VERSION 5.7 ;
  NOWIREEXTENSIONATPIN ON ;
  DIVIDERCHAR "/" ;
  BUSBITCHARS "[]" ;
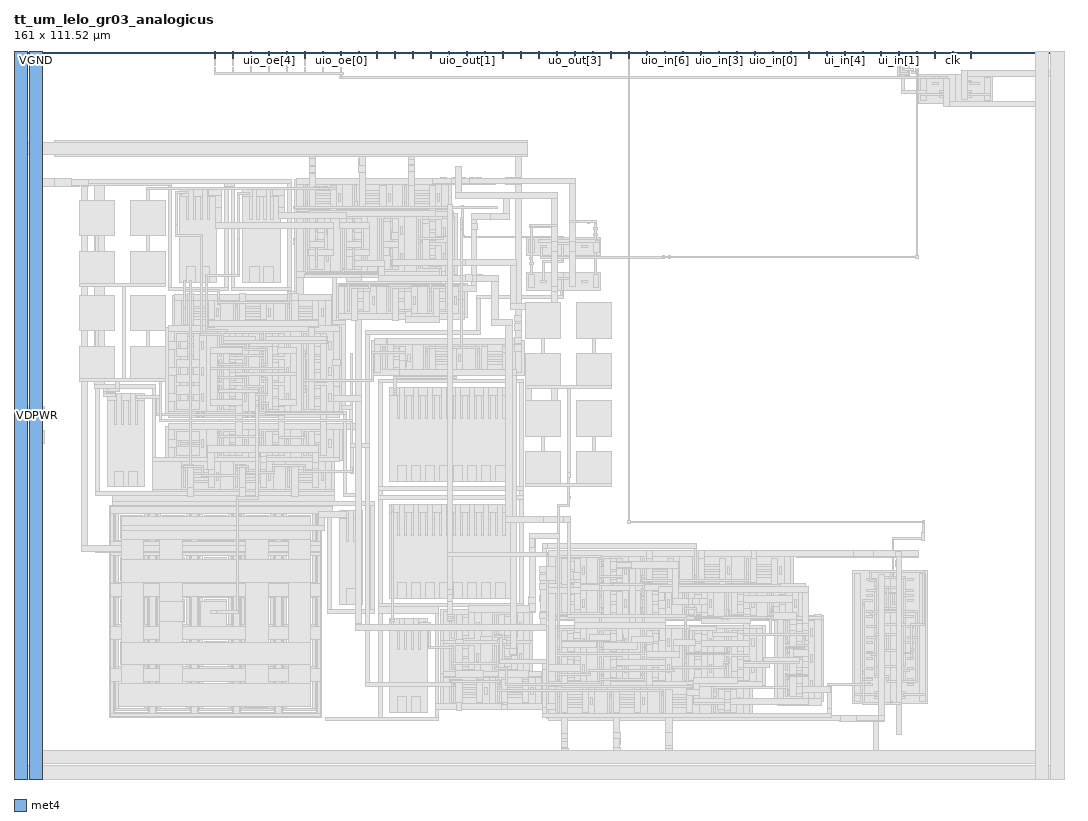
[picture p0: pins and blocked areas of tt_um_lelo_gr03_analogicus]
MACRO tt_um_lelo_gr03_analogicus
  CLASS BLOCK ;
  FOREIGN tt_um_lelo_gr03_analogicus ;
  ORIGIN 0.000 0.000 ;
  SIZE 161.000 BY 111.520 ;
  PIN uo_out[7]
    DIRECTION OUTPUT ;
    USE SIGNAL ;
    PORT
      LAYER met4 ;
        RECT 74.830 110.520 75.130 111.520 ;
    END
  END uo_out[7]
  PIN uo_out[6]
    DIRECTION OUTPUT ;
    USE SIGNAL ;
    PORT
      LAYER met4 ;
        RECT 77.590 110.520 77.890 111.520 ;
    END
  END uo_out[6]
  PIN uo_out[5]
    DIRECTION OUTPUT ;
    USE SIGNAL ;
    PORT
      LAYER met4 ;
        RECT 80.350 110.520 80.650 111.520 ;
    END
  END uo_out[5]
  PIN uo_out[4]
    DIRECTION OUTPUT ;
    USE SIGNAL ;
    PORT
      LAYER met4 ;
        RECT 83.110 110.520 83.410 111.520 ;
    END
  END uo_out[4]
  PIN uo_out[3]
    DIRECTION OUTPUT ;
    USE SIGNAL ;
    PORT
      LAYER met4 ;
        RECT 85.870 110.520 86.170 111.520 ;
    END
  END uo_out[3]
  PIN uo_out[2]
    DIRECTION OUTPUT ;
    USE SIGNAL ;
    PORT
      LAYER met4 ;
        RECT 88.630 110.520 88.930 111.520 ;
    END
  END uo_out[2]
  PIN uo_out[1]
    DIRECTION OUTPUT ;
    USE SIGNAL ;
    PORT
      LAYER met4 ;
        RECT 91.390 110.520 91.690 111.520 ;
    END
  END uo_out[1]
  PIN uo_out[0]
    DIRECTION OUTPUT ;
    USE SIGNAL ;
    ANTENNAGATEAREA 0.288000 ;
    ANTENNADIFFAREA 0.936000 ;
    PORT
      LAYER met4 ;
        RECT 94.150 110.520 94.450 111.520 ;
    END
  END uo_out[0]
  PIN uio_out[7]
    DIRECTION OUTPUT ;
    USE SIGNAL ;
    PORT
      LAYER met4 ;
        RECT 52.750 110.520 53.050 111.520 ;
    END
  END uio_out[7]
  PIN uio_out[6]
    DIRECTION OUTPUT ;
    USE SIGNAL ;
    PORT
      LAYER met4 ;
        RECT 55.510 110.520 55.810 111.520 ;
    END
  END uio_out[6]
  PIN uio_out[5]
    DIRECTION OUTPUT ;
    USE SIGNAL ;
    PORT
      LAYER met4 ;
        RECT 58.270 110.520 58.570 111.520 ;
    END
  END uio_out[5]
  PIN uio_out[4]
    DIRECTION OUTPUT ;
    USE SIGNAL ;
    PORT
      LAYER met4 ;
        RECT 61.030 110.520 61.330 111.520 ;
    END
  END uio_out[4]
  PIN uio_out[3]
    DIRECTION OUTPUT ;
    USE SIGNAL ;
    PORT
      LAYER met4 ;
        RECT 63.790 110.520 64.090 111.520 ;
    END
  END uio_out[3]
  PIN uio_out[2]
    DIRECTION OUTPUT ;
    USE SIGNAL ;
    PORT
      LAYER met4 ;
        RECT 66.550 110.520 66.850 111.520 ;
    END
  END uio_out[2]
  PIN uio_out[1]
    DIRECTION OUTPUT ;
    USE SIGNAL ;
    PORT
      LAYER met4 ;
        RECT 69.310 110.520 69.610 111.520 ;
    END
  END uio_out[1]
  PIN uio_out[0]
    DIRECTION OUTPUT ;
    USE SIGNAL ;
    PORT
      LAYER met4 ;
        RECT 72.070 110.520 72.370 111.520 ;
    END
  END uio_out[0]
  PIN uio_oe[7]
    DIRECTION OUTPUT ;
    USE SIGNAL ;
    PORT
      LAYER met4 ;
        RECT 30.670 110.520 30.970 111.520 ;
    END
  END uio_oe[7]
  PIN uio_oe[6]
    DIRECTION OUTPUT ;
    USE SIGNAL ;
    PORT
      LAYER met4 ;
        RECT 33.430 110.520 33.730 111.520 ;
    END
  END uio_oe[6]
  PIN uio_oe[5]
    DIRECTION OUTPUT ;
    USE SIGNAL ;
    PORT
      LAYER met4 ;
        RECT 36.190 110.520 36.490 111.520 ;
    END
  END uio_oe[5]
  PIN uio_oe[4]
    DIRECTION OUTPUT ;
    USE SIGNAL ;
    PORT
      LAYER met4 ;
        RECT 38.950 110.520 39.250 111.520 ;
    END
  END uio_oe[4]
  PIN uio_oe[3]
    DIRECTION OUTPUT ;
    USE SIGNAL ;
    PORT
      LAYER met4 ;
        RECT 41.710 110.520 42.010 111.520 ;
    END
  END uio_oe[3]
  PIN uio_oe[2]
    DIRECTION OUTPUT ;
    USE SIGNAL ;
    PORT
      LAYER met4 ;
        RECT 44.470 110.520 44.770 111.520 ;
    END
  END uio_oe[2]
  PIN uio_oe[1]
    DIRECTION OUTPUT ;
    USE SIGNAL ;
    PORT
      LAYER met4 ;
        RECT 47.230 110.520 47.530 111.520 ;
    END
  END uio_oe[1]
  PIN uio_oe[0]
    DIRECTION OUTPUT ;
    USE SIGNAL ;
    PORT
      LAYER met4 ;
        RECT 49.990 110.520 50.290 111.520 ;
    END
  END uio_oe[0]
  PIN VDPWR
    DIRECTION INOUT ;
    USE POWER ;
    PORT
      LAYER met4 ;
        RECT 0.000 0.000 2.000 111.520 ;
    END
  END VDPWR
  PIN VGND
    DIRECTION INOUT ;
    USE GROUND ;
    PORT
      LAYER met4 ;
        RECT 2.400 0.000 4.400 111.520 ;
    END
  END VGND
  PIN ui_in[7]
    DIRECTION INPUT ;
    USE SIGNAL ;
    PORT
      LAYER met4 ;
        RECT 118.990 110.520 119.290 111.520 ;
    END
  END ui_in[7]
  PIN ui_in[6]
    DIRECTION INPUT ;
    USE SIGNAL ;
    PORT
      LAYER met4 ;
        RECT 121.750 110.520 122.050 111.520 ;
    END
  END ui_in[6]
  PIN ui_in[5]
    DIRECTION INPUT ;
    USE SIGNAL ;
    PORT
      LAYER met4 ;
        RECT 124.510 110.520 124.810 111.520 ;
    END
  END ui_in[5]
  PIN ui_in[4]
    DIRECTION INPUT ;
    USE SIGNAL ;
    PORT
      LAYER met4 ;
        RECT 127.270 110.520 127.570 111.520 ;
    END
  END ui_in[4]
  PIN ui_in[3]
    DIRECTION INPUT ;
    USE SIGNAL ;
    PORT
      LAYER met4 ;
        RECT 130.030 110.520 130.330 111.520 ;
    END
  END ui_in[3]
  PIN ui_in[2]
    DIRECTION INPUT ;
    USE SIGNAL ;
    PORT
      LAYER met4 ;
        RECT 132.790 110.520 133.090 111.520 ;
    END
  END ui_in[2]
  PIN ui_in[1]
    DIRECTION INPUT ;
    USE SIGNAL ;
    PORT
      LAYER met4 ;
        RECT 135.550 110.520 135.850 111.520 ;
    END
  END ui_in[1]
  PIN ui_in[0]
    DIRECTION INPUT ;
    USE SIGNAL ;
    ANTENNAGATEAREA 0.490500 ;
    ANTENNADIFFAREA 0.202500 ;
    PORT
      LAYER met4 ;
        RECT 138.310 110.520 138.610 111.520 ;
    END
  END ui_in[0]
  PIN uio_in[7]
    DIRECTION INPUT ;
    USE SIGNAL ;
    PORT
      LAYER met4 ;
        RECT 96.910 110.520 97.210 111.520 ;
    END
  END uio_in[7]
  PIN uio_in[6]
    DIRECTION INPUT ;
    USE SIGNAL ;
    PORT
      LAYER met4 ;
        RECT 99.670 110.520 99.970 111.520 ;
    END
  END uio_in[6]
  PIN uio_in[5]
    DIRECTION INPUT ;
    USE SIGNAL ;
    PORT
      LAYER met4 ;
        RECT 102.430 110.520 102.730 111.520 ;
    END
  END uio_in[5]
  PIN uio_in[4]
    DIRECTION INPUT ;
    USE SIGNAL ;
    PORT
      LAYER met4 ;
        RECT 105.190 110.520 105.490 111.520 ;
    END
  END uio_in[4]
  PIN uio_in[3]
    DIRECTION INPUT ;
    USE SIGNAL ;
    PORT
      LAYER met4 ;
        RECT 107.950 110.520 108.250 111.520 ;
    END
  END uio_in[3]
  PIN uio_in[2]
    DIRECTION INPUT ;
    USE SIGNAL ;
    PORT
      LAYER met4 ;
        RECT 110.710 110.520 111.010 111.520 ;
    END
  END uio_in[2]
  PIN uio_in[1]
    DIRECTION INPUT ;
    USE SIGNAL ;
    PORT
      LAYER met4 ;
        RECT 113.470 110.520 113.770 111.520 ;
    END
  END uio_in[1]
  PIN uio_in[0]
    DIRECTION INPUT ;
    USE SIGNAL ;
    PORT
      LAYER met4 ;
        RECT 116.230 110.520 116.530 111.520 ;
    END
  END uio_in[0]
  PIN ena
    DIRECTION INPUT ;
    USE SIGNAL ;
    PORT
      LAYER met4 ;
        RECT 146.590 110.520 146.890 111.520 ;
    END
  END ena
  PIN rst_n
    DIRECTION INPUT ;
    USE SIGNAL ;
    PORT
      LAYER met4 ;
        RECT 141.070 110.520 141.370 111.520 ;
    END
  END rst_n
  PIN clk
    DIRECTION INPUT ;
    USE SIGNAL ;
    PORT
      LAYER met4 ;
        RECT 143.830 110.520 144.130 111.520 ;
    END
  END clk
  OBS
      LAYER pwell ;
        RECT 135.535 107.915 137.365 109.745 ;
        RECT 138.680 103.630 144.380 108.030 ;
      LAYER nwell ;
        RECT 144.380 103.630 150.080 108.030 ;
      LAYER pwell ;
        RECT 25.360 76.170 31.120 90.570 ;
        RECT 35.060 76.170 40.820 90.570 ;
      LAYER nwell ;
        RECT 42.940 86.650 67.020 91.850 ;
        RECT 42.940 77.370 67.940 86.650 ;
      LAYER pwell ;
        RECT 78.600 80.270 84.300 83.070 ;
      LAYER nwell ;
        RECT 84.300 80.270 90.000 83.070 ;
        RECT 42.940 77.270 61.300 77.370 ;
        RECT 24.240 69.165 49.120 74.165 ;
      LAYER pwell ;
        RECT 49.340 70.770 69.540 76.050 ;
        RECT 78.580 74.920 84.280 77.720 ;
      LAYER nwell ;
        RECT 84.280 74.920 89.980 77.720 ;
      LAYER pwell ;
        RECT 14.260 44.785 20.020 59.185 ;
      LAYER nwell ;
        RECT 23.240 55.885 50.340 69.165 ;
        RECT 54.850 61.910 78.230 67.190 ;
      LAYER pwell ;
        RECT 23.240 48.805 50.340 54.085 ;
        RECT 24.240 43.805 49.120 48.805 ;
        RECT 57.650 45.610 76.370 60.010 ;
        RECT 14.660 41.185 47.120 41.950 ;
        RECT 14.660 36.015 15.425 41.185 ;
        RECT 20.595 36.015 21.865 41.185 ;
        RECT 27.035 36.015 28.305 41.185 ;
        RECT 33.475 36.015 34.745 41.185 ;
        RECT 39.915 36.015 41.185 41.185 ;
        RECT 46.355 36.015 47.120 41.185 ;
        RECT 14.660 34.745 47.120 36.015 ;
        RECT 14.660 29.575 15.425 34.745 ;
        RECT 20.595 29.575 21.865 34.745 ;
        RECT 27.035 29.575 28.305 34.745 ;
        RECT 33.475 29.575 34.745 34.745 ;
        RECT 39.915 29.575 41.185 34.745 ;
        RECT 46.355 29.575 47.120 34.745 ;
        RECT 14.660 28.305 47.120 29.575 ;
        RECT 14.660 23.135 15.425 28.305 ;
        RECT 20.595 23.135 21.865 28.305 ;
        RECT 27.035 23.135 28.305 28.305 ;
        RECT 33.475 23.135 34.745 28.305 ;
        RECT 39.915 23.135 41.185 28.305 ;
        RECT 46.355 23.135 47.120 28.305 ;
        RECT 49.860 26.770 53.460 41.170 ;
        RECT 57.650 27.720 76.370 42.120 ;
      LAYER nwell ;
        RECT 81.590 29.590 119.470 34.590 ;
      LAYER pwell ;
        RECT 71.940 26.060 79.540 26.100 ;
        RECT 14.660 21.865 47.120 23.135 ;
        RECT 14.660 16.695 15.425 21.865 ;
        RECT 20.595 16.695 21.865 21.865 ;
        RECT 27.035 16.695 28.305 21.865 ;
        RECT 33.475 16.695 34.745 21.865 ;
        RECT 39.915 16.695 41.185 21.865 ;
        RECT 46.355 16.695 47.120 21.865 ;
        RECT 14.660 15.425 47.120 16.695 ;
        RECT 14.660 10.255 15.425 15.425 ;
        RECT 20.595 10.255 21.865 15.425 ;
        RECT 27.035 10.255 28.305 15.425 ;
        RECT 33.475 10.255 34.745 15.425 ;
        RECT 39.915 10.255 41.185 15.425 ;
        RECT 46.355 10.255 47.120 15.425 ;
        RECT 14.660 9.490 47.120 10.255 ;
        RECT 57.650 10.230 63.410 24.630 ;
        RECT 65.430 21.290 79.540 26.060 ;
      LAYER nwell ;
        RECT 81.590 25.090 121.690 29.590 ;
        RECT 81.590 24.310 124.190 25.090 ;
      LAYER pwell ;
        RECT 65.400 16.130 79.540 21.290 ;
        RECT 65.380 10.850 81.300 16.130 ;
        RECT 81.590 14.310 115.190 23.590 ;
        RECT 81.590 9.310 113.190 14.310 ;
      LAYER nwell ;
        RECT 116.590 11.810 124.190 24.310 ;
      LAYER pwell ;
        RECT 128.640 11.520 134.340 31.920 ;
      LAYER nwell ;
        RECT 134.340 11.520 140.040 31.920 ;
      LAYER li1 ;
        RECT 135.715 109.395 137.185 109.565 ;
        RECT 135.715 108.265 135.885 109.395 ;
        RECT 136.205 108.665 136.695 108.995 ;
        RECT 137.015 108.265 137.185 109.395 ;
        RECT 135.715 108.095 137.185 108.265 ;
        RECT 136.110 105.600 136.500 108.095 ;
        RECT 138.980 105.600 139.880 107.630 ;
        RECT 142.100 107.380 143.200 107.680 ;
        RECT 142.900 107.180 143.200 107.380 ;
        RECT 142.580 106.880 143.480 107.180 ;
        RECT 145.280 106.880 146.780 107.180 ;
        RECT 146.480 106.780 146.780 106.880 ;
        RECT 140.780 106.480 141.680 106.780 ;
        RECT 146.480 106.480 147.980 106.780 ;
        RECT 142.580 106.380 143.420 106.400 ;
        RECT 145.280 106.380 146.120 106.400 ;
        RECT 142.580 106.080 143.480 106.380 ;
        RECT 145.280 106.080 146.180 106.380 ;
        RECT 136.110 105.180 139.880 105.600 ;
        RECT 142.580 105.580 143.420 105.600 ;
        RECT 145.280 105.580 146.120 105.600 ;
        RECT 141.980 105.280 143.480 105.580 ;
        RECT 145.280 105.280 146.780 105.580 ;
        RECT 141.980 105.180 142.280 105.280 ;
        RECT 136.110 105.050 142.280 105.180 ;
        RECT 138.980 104.880 142.280 105.050 ;
        RECT 138.980 104.030 139.880 104.880 ;
        RECT 141.980 104.780 142.280 104.880 ;
        RECT 146.480 105.180 146.780 105.280 ;
        RECT 148.880 105.180 149.780 107.630 ;
        RECT 146.480 104.880 149.780 105.180 ;
        RECT 142.580 104.780 143.420 104.800 ;
        RECT 145.280 104.780 146.120 104.800 ;
        RECT 146.480 104.780 146.780 104.880 ;
        RECT 141.980 104.480 143.480 104.780 ;
        RECT 145.280 104.480 146.780 104.780 ;
        RECT 148.880 104.030 149.780 104.880 ;
        RECT 64.200 92.050 65.020 92.110 ;
        RECT 65.430 92.050 66.250 92.110 ;
        RECT 9.070 91.890 24.200 91.930 ;
        RECT 9.070 91.870 32.860 91.890 ;
        RECT 33.320 91.870 42.560 91.890 ;
        RECT 9.070 91.330 42.560 91.870 ;
        RECT 9.070 90.970 24.200 91.330 ;
        RECT 10.370 35.870 11.330 90.970 ;
        RECT 12.370 60.505 13.880 90.970 ;
        RECT 23.620 75.410 24.180 90.970 ;
        RECT 32.300 90.870 33.880 91.330 ;
        RECT 25.360 89.370 26.800 90.570 ;
        RECT 26.440 85.770 26.800 89.370 ;
        RECT 27.520 89.370 28.960 90.570 ;
        RECT 27.520 85.770 27.880 89.370 ;
        RECT 28.600 85.770 28.960 89.370 ;
        RECT 29.680 89.370 31.120 90.570 ;
        RECT 29.680 85.770 30.040 89.370 ;
        RECT 26.440 76.170 27.880 78.570 ;
        RECT 28.600 76.170 30.040 78.570 ;
        RECT 32.300 75.410 32.860 90.870 ;
        RECT 23.620 74.850 32.860 75.410 ;
        RECT 33.320 75.410 33.880 90.870 ;
        RECT 35.060 89.370 36.500 90.570 ;
        RECT 36.140 85.770 36.500 89.370 ;
        RECT 37.220 89.370 38.660 90.570 ;
        RECT 37.220 85.770 37.580 89.370 ;
        RECT 38.300 85.770 38.660 89.370 ;
        RECT 39.380 89.370 40.820 90.570 ;
        RECT 39.380 85.770 39.740 89.370 ;
        RECT 36.140 76.170 37.580 78.570 ;
        RECT 38.300 76.170 39.740 78.570 ;
        RECT 42.000 75.410 42.560 91.330 ;
        RECT 43.380 91.090 73.760 92.050 ;
        RECT 43.380 87.250 44.340 91.090 ;
        RECT 48.270 90.400 48.610 90.740 ;
        RECT 48.970 90.400 49.310 90.740 ;
        RECT 45.300 89.810 48.820 90.210 ;
        RECT 44.660 88.610 44.980 89.810 ;
        RECT 45.940 89.010 49.460 89.410 ;
        RECT 49.780 88.610 50.100 89.810 ;
        RECT 45.300 88.210 48.820 88.610 ;
        RECT 50.420 87.250 51.940 91.090 ;
        RECT 52.900 89.810 56.420 90.210 ;
        RECT 52.260 88.610 52.580 89.810 ;
        RECT 53.540 89.010 57.060 89.410 ;
        RECT 57.380 88.610 57.700 89.810 ;
        RECT 52.900 88.210 56.420 88.610 ;
        RECT 58.020 87.250 59.540 91.090 ;
        RECT 60.500 89.810 64.020 90.210 ;
        RECT 59.860 88.610 60.180 89.810 ;
        RECT 61.140 89.010 64.660 89.410 ;
        RECT 64.980 88.610 65.300 89.810 ;
        RECT 60.500 88.210 64.020 88.610 ;
        RECT 65.620 87.250 66.620 91.090 ;
        RECT 43.360 86.950 66.620 87.250 ;
        RECT 43.360 86.290 67.420 86.950 ;
        RECT 33.320 74.850 42.560 75.410 ;
        RECT 43.380 77.850 44.340 86.290 ;
        RECT 45.300 85.510 46.900 85.910 ;
        RECT 44.660 83.510 44.980 84.710 ;
        RECT 45.940 83.910 47.540 84.310 ;
        RECT 47.860 83.510 48.180 84.710 ;
        RECT 45.300 82.310 46.900 82.710 ;
        RECT 45.300 81.310 46.900 81.710 ;
        RECT 44.660 79.310 44.980 80.510 ;
        RECT 45.940 79.710 47.540 80.110 ;
        RECT 47.860 79.310 48.180 80.510 ;
        RECT 45.300 78.110 46.900 78.510 ;
        RECT 48.500 77.850 50.040 86.290 ;
        RECT 51.000 85.510 52.600 85.910 ;
        RECT 50.360 83.510 50.680 84.710 ;
        RECT 51.640 83.910 53.240 84.310 ;
        RECT 53.560 83.510 53.880 84.710 ;
        RECT 51.000 82.310 52.600 82.710 ;
        RECT 51.000 81.310 52.600 81.710 ;
        RECT 50.360 79.310 50.680 80.510 ;
        RECT 51.640 79.710 53.240 80.110 ;
        RECT 53.560 79.310 53.880 80.510 ;
        RECT 51.000 78.110 52.600 78.510 ;
        RECT 54.200 77.850 55.740 86.290 ;
        RECT 56.700 85.510 58.300 85.910 ;
        RECT 56.060 83.510 56.380 84.710 ;
        RECT 57.340 83.910 58.940 84.310 ;
        RECT 59.260 83.510 59.580 84.710 ;
        RECT 56.700 82.310 58.300 82.710 ;
        RECT 56.700 81.310 58.300 81.710 ;
        RECT 56.060 79.310 56.380 80.510 ;
        RECT 57.340 79.710 58.940 80.110 ;
        RECT 59.260 79.310 59.580 80.510 ;
        RECT 56.700 78.110 58.300 78.510 ;
        RECT 59.900 77.850 61.740 86.290 ;
        RECT 65.660 86.210 67.420 86.290 ;
        RECT 65.660 85.990 67.500 86.210 ;
        RECT 62.700 85.410 64.940 85.810 ;
        RECT 62.060 83.410 62.380 84.610 ;
        RECT 63.340 83.810 65.580 84.210 ;
        RECT 65.900 83.410 66.220 84.610 ;
        RECT 62.700 82.210 64.940 82.610 ;
        RECT 62.700 81.410 64.940 81.810 ;
        RECT 62.060 79.410 62.380 80.610 ;
        RECT 63.340 79.810 65.580 80.210 ;
        RECT 65.900 79.410 66.220 80.610 ;
        RECT 62.700 78.210 64.940 78.610 ;
        RECT 66.540 77.850 67.500 85.990 ;
        RECT 68.610 83.260 68.910 83.940 ;
        RECT 68.610 82.960 84.290 83.260 ;
        RECT 78.900 80.670 79.800 82.670 ;
        RECT 83.990 82.220 84.290 82.960 ;
        RECT 88.950 82.670 89.350 84.610 ;
        RECT 88.800 82.640 89.700 82.670 ;
        RECT 88.720 82.300 89.700 82.640 ;
        RECT 82.500 81.920 86.100 82.220 ;
        RECT 80.700 81.520 81.600 81.820 ;
        RECT 81.280 81.500 81.520 81.520 ;
        RECT 82.500 81.420 83.340 81.440 ;
        RECT 82.500 81.120 83.400 81.420 ;
        RECT 43.380 76.890 67.520 77.850 ;
        RECT 79.130 77.320 79.530 80.670 ;
        RECT 83.990 79.480 84.290 81.920 ;
        RECT 87.000 81.520 87.900 81.820 ;
        RECT 85.200 81.420 86.040 81.440 ;
        RECT 85.200 81.120 86.100 81.420 ;
        RECT 88.800 80.670 89.700 82.300 ;
        RECT 81.080 79.180 84.290 79.480 ;
        RECT 43.380 74.365 44.340 76.890 ;
        RECT 49.840 75.630 69.040 75.870 ;
        RECT 49.840 75.610 69.050 75.630 ;
        RECT 49.780 75.470 69.100 75.610 ;
        RECT 24.680 73.405 48.680 74.365 ;
        RECT 24.680 69.605 25.640 73.405 ;
        RECT 26.600 72.125 30.120 72.525 ;
        RECT 25.960 70.925 26.280 72.125 ;
        RECT 27.240 71.325 30.760 71.725 ;
        RECT 31.080 70.925 31.400 72.125 ;
        RECT 26.600 70.525 30.120 70.925 ;
        RECT 31.720 69.605 33.640 73.405 ;
        RECT 34.600 72.125 38.120 72.525 ;
        RECT 33.960 70.925 34.280 72.125 ;
        RECT 35.240 71.325 38.760 71.725 ;
        RECT 39.080 70.925 39.400 72.125 ;
        RECT 34.600 70.525 38.120 70.925 ;
        RECT 39.720 69.605 41.640 73.405 ;
        RECT 42.600 72.125 46.120 72.525 ;
        RECT 41.960 70.925 42.280 72.125 ;
        RECT 43.240 71.325 46.760 71.725 ;
        RECT 47.080 70.925 47.400 72.125 ;
        RECT 42.600 70.525 46.120 70.925 ;
        RECT 47.720 69.605 48.680 73.405 ;
        RECT 49.780 71.350 50.740 75.470 ;
        RECT 51.700 74.810 53.940 75.210 ;
        RECT 51.060 72.810 51.380 74.010 ;
        RECT 52.340 73.210 54.580 73.610 ;
        RECT 54.900 72.810 55.220 74.010 ;
        RECT 51.700 71.610 53.940 72.010 ;
        RECT 55.540 71.350 57.040 75.470 ;
        RECT 58.000 74.810 60.240 75.210 ;
        RECT 57.360 72.810 57.680 74.010 ;
        RECT 58.640 73.210 60.880 73.610 ;
        RECT 61.200 72.810 61.520 74.010 ;
        RECT 58.000 71.610 60.240 72.010 ;
        RECT 61.840 71.350 63.340 75.470 ;
        RECT 64.300 74.810 66.540 75.210 ;
        RECT 63.660 72.810 63.980 74.010 ;
        RECT 64.940 73.210 67.180 73.610 ;
        RECT 67.500 72.810 67.820 74.010 ;
        RECT 64.300 71.610 66.540 72.010 ;
        RECT 68.140 71.350 69.100 75.470 ;
        RECT 78.880 75.320 79.780 77.320 ;
        RECT 81.080 76.470 81.380 79.180 ;
        RECT 88.950 77.320 89.350 80.670 ;
        RECT 82.480 76.570 86.080 76.870 ;
        RECT 80.680 76.170 81.580 76.470 ;
        RECT 82.480 76.070 83.320 76.090 ;
        RECT 82.480 75.770 83.380 76.070 ;
        RECT 83.900 74.890 84.200 76.570 ;
        RECT 86.980 76.170 87.880 76.470 ;
        RECT 85.180 76.070 86.020 76.090 ;
        RECT 85.180 75.770 86.080 76.070 ;
        RECT 88.780 75.320 89.680 77.320 ;
        RECT 83.870 73.880 84.200 74.890 ;
        RECT 83.870 73.850 84.170 73.880 ;
        RECT 49.780 70.390 69.120 71.350 ;
        RECT 23.680 68.645 49.905 69.605 ;
        RECT 23.680 67.125 24.640 68.645 ;
        RECT 25.600 67.925 27.840 68.325 ;
        RECT 23.680 65.925 25.280 67.125 ;
        RECT 26.240 66.325 28.480 66.725 ;
        RECT 28.800 65.925 29.120 67.125 ;
        RECT 23.680 63.125 24.640 65.925 ;
        RECT 25.600 64.725 27.840 65.125 ;
        RECT 25.600 63.925 27.840 64.325 ;
        RECT 23.680 61.925 25.280 63.125 ;
        RECT 26.240 62.325 28.480 62.725 ;
        RECT 28.800 61.925 29.120 63.125 ;
        RECT 12.370 59.945 21.760 60.505 ;
        RECT 12.520 44.025 13.080 59.945 ;
        RECT 14.260 57.985 15.700 59.185 ;
        RECT 15.340 54.385 15.700 57.985 ;
        RECT 16.420 57.985 17.860 59.185 ;
        RECT 16.420 54.385 16.780 57.985 ;
        RECT 17.500 54.385 17.860 57.985 ;
        RECT 18.580 57.985 20.020 59.185 ;
        RECT 18.580 54.385 18.940 57.985 ;
        RECT 21.200 49.265 21.760 59.945 ;
        RECT 23.680 59.125 24.640 61.925 ;
        RECT 25.600 60.725 27.840 61.125 ;
        RECT 25.600 59.925 27.840 60.325 ;
        RECT 23.680 57.925 25.280 59.125 ;
        RECT 26.240 58.325 28.480 58.725 ;
        RECT 28.800 57.925 29.120 59.125 ;
        RECT 23.680 56.365 24.640 57.925 ;
        RECT 25.600 56.725 27.840 57.125 ;
        RECT 29.440 56.365 31.140 68.645 ;
        RECT 32.100 67.925 34.340 68.325 ;
        RECT 31.460 65.925 31.780 67.125 ;
        RECT 32.740 66.325 34.980 66.725 ;
        RECT 35.300 65.925 35.620 67.125 ;
        RECT 32.100 64.725 34.340 65.125 ;
        RECT 32.100 63.925 34.340 64.325 ;
        RECT 31.460 61.925 31.780 63.125 ;
        RECT 32.740 62.325 34.980 62.725 ;
        RECT 35.300 61.925 35.620 63.125 ;
        RECT 32.100 60.725 34.340 61.125 ;
        RECT 32.100 59.925 34.340 60.325 ;
        RECT 31.460 57.925 31.780 59.125 ;
        RECT 32.740 58.325 34.980 58.725 ;
        RECT 35.300 57.925 35.620 59.125 ;
        RECT 32.100 56.725 34.340 57.125 ;
        RECT 35.940 56.365 37.640 68.645 ;
        RECT 38.600 67.925 40.840 68.325 ;
        RECT 37.960 65.925 38.280 67.125 ;
        RECT 39.240 66.325 41.480 66.725 ;
        RECT 41.800 65.925 42.120 67.125 ;
        RECT 38.600 64.725 40.840 65.125 ;
        RECT 38.600 63.925 40.840 64.325 ;
        RECT 37.960 61.925 38.280 63.125 ;
        RECT 39.240 62.325 41.480 62.725 ;
        RECT 41.800 61.925 42.120 63.125 ;
        RECT 38.600 60.725 40.840 61.125 ;
        RECT 38.600 59.925 40.840 60.325 ;
        RECT 37.960 57.925 38.280 59.125 ;
        RECT 39.240 58.325 41.480 58.725 ;
        RECT 41.800 57.925 42.120 59.125 ;
        RECT 38.600 56.725 40.840 57.125 ;
        RECT 42.440 56.365 44.140 68.645 ;
        RECT 45.100 67.925 47.340 68.325 ;
        RECT 44.460 65.925 44.780 67.125 ;
        RECT 45.740 66.325 47.980 66.725 ;
        RECT 48.300 65.925 48.620 67.125 ;
        RECT 45.100 64.725 47.340 65.125 ;
        RECT 48.940 64.340 49.900 68.645 ;
        RECT 45.100 63.925 47.340 64.325 ;
        RECT 44.460 61.925 44.780 63.125 ;
        RECT 45.740 62.325 47.980 62.725 ;
        RECT 48.300 61.925 48.620 63.125 ;
        RECT 48.940 61.930 49.930 64.340 ;
        RECT 45.100 60.725 47.340 61.125 ;
        RECT 45.100 59.925 47.340 60.325 ;
        RECT 44.460 57.925 44.780 59.125 ;
        RECT 45.740 58.325 47.980 58.725 ;
        RECT 48.300 57.925 48.620 59.125 ;
        RECT 45.100 56.725 47.340 57.125 ;
        RECT 48.940 56.365 49.900 61.930 ;
        RECT 23.680 55.405 49.900 56.365 ;
        RECT 52.320 54.535 53.280 70.390 ;
        RECT 76.860 67.590 77.760 67.730 ;
        RECT 55.290 66.630 77.830 67.590 ;
        RECT 55.290 62.350 56.250 66.630 ;
        RECT 57.210 65.950 59.450 66.350 ;
        RECT 56.570 63.950 56.890 65.150 ;
        RECT 57.850 64.350 60.090 64.750 ;
        RECT 60.410 63.950 60.730 65.150 ;
        RECT 57.210 62.750 59.450 63.150 ;
        RECT 61.050 62.350 62.750 66.630 ;
        RECT 63.710 65.150 67.230 65.550 ;
        RECT 63.070 63.950 63.390 65.150 ;
        RECT 64.350 64.350 67.870 64.750 ;
        RECT 68.190 63.950 68.510 65.150 ;
        RECT 63.710 63.550 67.230 63.950 ;
        RECT 68.830 62.350 70.750 66.630 ;
        RECT 71.710 65.150 75.230 65.550 ;
        RECT 71.070 63.950 71.390 65.150 ;
        RECT 72.350 64.350 75.870 64.750 ;
        RECT 76.190 63.950 76.510 65.150 ;
        RECT 71.710 63.550 75.230 63.950 ;
        RECT 76.830 62.350 77.790 66.630 ;
        RECT 23.680 53.575 53.280 54.535 ;
        RECT 55.910 60.770 78.110 61.330 ;
        RECT 23.680 52.045 24.640 53.575 ;
        RECT 25.600 52.845 27.840 53.245 ;
        RECT 23.680 50.845 25.280 52.045 ;
        RECT 26.240 51.245 28.480 51.645 ;
        RECT 28.800 50.845 29.120 52.045 ;
        RECT 23.680 49.345 24.640 50.845 ;
        RECT 25.600 49.645 27.840 50.045 ;
        RECT 23.680 49.265 24.650 49.345 ;
        RECT 29.440 49.265 31.140 53.575 ;
        RECT 32.100 52.845 34.340 53.245 ;
        RECT 31.450 52.335 34.560 52.655 ;
        RECT 31.460 50.845 31.780 52.045 ;
        RECT 32.740 51.245 34.980 51.645 ;
        RECT 35.300 50.845 35.620 52.045 ;
        RECT 32.100 49.645 34.340 50.045 ;
        RECT 35.940 49.265 37.640 53.575 ;
        RECT 38.600 52.845 40.840 53.245 ;
        RECT 37.960 50.845 38.280 52.045 ;
        RECT 39.240 51.245 41.480 51.645 ;
        RECT 41.800 50.845 42.120 52.045 ;
        RECT 38.600 49.645 40.840 50.045 ;
        RECT 42.440 49.265 44.140 53.575 ;
        RECT 45.100 52.845 47.340 53.245 ;
        RECT 44.460 50.845 44.780 52.045 ;
        RECT 45.740 51.245 47.980 51.645 ;
        RECT 48.300 50.845 48.620 52.045 ;
        RECT 45.100 49.645 47.340 50.045 ;
        RECT 48.940 49.265 49.900 53.575 ;
        RECT 21.200 48.680 49.900 49.265 ;
        RECT 15.340 44.785 16.780 47.185 ;
        RECT 17.500 44.785 18.940 47.185 ;
        RECT 21.200 44.315 25.640 48.680 ;
        RECT 26.600 47.045 30.120 47.445 ;
        RECT 25.960 45.845 26.280 47.045 ;
        RECT 27.240 46.245 30.760 46.645 ;
        RECT 31.080 45.845 31.400 47.045 ;
        RECT 26.600 45.445 30.120 45.845 ;
        RECT 31.720 44.315 33.640 48.680 ;
        RECT 34.600 47.045 38.120 47.445 ;
        RECT 33.960 45.845 34.280 47.045 ;
        RECT 35.240 46.245 38.760 46.645 ;
        RECT 39.080 45.845 39.400 47.045 ;
        RECT 34.600 45.445 38.120 45.845 ;
        RECT 39.720 44.315 41.640 48.680 ;
        RECT 42.600 47.045 46.120 47.445 ;
        RECT 41.960 45.845 42.280 47.045 ;
        RECT 43.240 46.245 46.760 46.645 ;
        RECT 47.080 45.845 47.400 47.045 ;
        RECT 42.600 45.445 46.120 45.845 ;
        RECT 47.720 44.315 48.680 48.680 ;
        RECT 55.910 44.850 56.470 60.770 ;
        RECT 57.650 58.810 59.090 60.010 ;
        RECT 58.730 55.210 59.090 58.810 ;
        RECT 59.810 58.810 61.250 60.010 ;
        RECT 59.810 55.210 60.170 58.810 ;
        RECT 60.890 55.210 61.250 58.810 ;
        RECT 61.970 58.810 63.410 60.010 ;
        RECT 61.970 55.210 62.330 58.810 ;
        RECT 63.050 55.210 63.410 58.810 ;
        RECT 64.130 58.810 65.570 60.010 ;
        RECT 64.130 55.210 64.490 58.810 ;
        RECT 65.210 55.210 65.570 58.810 ;
        RECT 66.290 58.810 67.730 60.010 ;
        RECT 66.290 55.210 66.650 58.810 ;
        RECT 67.370 55.210 67.730 58.810 ;
        RECT 68.450 58.810 69.890 60.010 ;
        RECT 68.450 55.210 68.810 58.810 ;
        RECT 69.530 55.210 69.890 58.810 ;
        RECT 70.610 58.810 72.050 60.010 ;
        RECT 70.610 55.210 70.970 58.810 ;
        RECT 71.690 55.210 72.050 58.810 ;
        RECT 72.770 58.810 74.210 60.010 ;
        RECT 72.770 55.210 73.130 58.810 ;
        RECT 73.850 55.210 74.210 58.810 ;
        RECT 74.930 58.810 76.370 60.010 ;
        RECT 74.930 55.210 75.290 58.810 ;
        RECT 58.730 45.610 60.170 48.010 ;
        RECT 60.890 45.610 62.330 48.010 ;
        RECT 63.050 45.610 64.490 48.010 ;
        RECT 65.210 45.610 66.650 48.010 ;
        RECT 67.370 45.610 68.810 48.010 ;
        RECT 69.530 45.610 70.970 48.010 ;
        RECT 71.690 45.610 73.130 48.010 ;
        RECT 73.850 45.610 75.290 48.010 ;
        RECT 77.550 44.850 78.110 60.770 ;
        RECT 21.200 44.025 49.160 44.315 ;
        RECT 12.520 43.465 49.160 44.025 ;
        RECT 15.050 42.490 49.160 43.465 ;
        RECT 55.910 44.290 78.110 44.850 ;
        RECT 55.910 43.440 56.470 44.290 ;
        RECT 77.550 43.440 78.110 44.290 ;
        RECT 55.910 42.880 78.110 43.440 ;
        RECT 15.050 41.930 55.200 42.490 ;
        RECT 15.050 41.820 48.880 41.930 ;
        RECT 14.790 40.770 48.880 41.820 ;
        RECT 14.790 36.350 15.285 40.770 ;
        RECT 15.605 40.645 20.415 40.770 ;
        RECT 15.605 36.555 15.965 40.645 ;
        RECT 16.275 36.865 19.745 40.335 ;
        RECT 20.055 36.555 20.415 40.645 ;
        RECT 15.605 36.350 20.415 36.555 ;
        RECT 20.735 36.350 21.725 40.770 ;
        RECT 22.045 40.645 26.855 40.770 ;
        RECT 22.045 36.555 22.405 40.645 ;
        RECT 22.715 36.865 26.185 40.335 ;
        RECT 26.495 36.555 26.855 40.645 ;
        RECT 22.045 36.350 26.855 36.555 ;
        RECT 27.175 36.350 28.165 40.770 ;
        RECT 28.485 40.645 33.295 40.770 ;
        RECT 28.485 36.555 28.845 40.645 ;
        RECT 29.155 36.865 32.625 40.335 ;
        RECT 32.935 36.555 33.295 40.645 ;
        RECT 28.485 36.350 33.295 36.555 ;
        RECT 33.615 36.350 34.605 40.770 ;
        RECT 34.925 40.645 39.735 40.770 ;
        RECT 34.925 36.555 35.285 40.645 ;
        RECT 35.595 36.865 39.065 40.335 ;
        RECT 39.375 36.555 39.735 40.645 ;
        RECT 34.925 36.350 39.735 36.555 ;
        RECT 40.055 36.350 41.045 40.770 ;
        RECT 41.365 40.645 46.175 40.770 ;
        RECT 41.365 36.555 41.725 40.645 ;
        RECT 42.035 36.865 45.505 40.335 ;
        RECT 45.815 36.555 46.175 40.645 ;
        RECT 41.365 36.350 46.175 36.555 ;
        RECT 46.495 36.350 46.990 40.770 ;
        RECT 14.790 35.870 46.990 36.350 ;
        RECT 10.370 34.910 46.990 35.870 ;
        RECT 12.510 34.720 46.990 34.910 ;
        RECT 14.790 34.330 46.990 34.720 ;
        RECT 14.790 29.970 15.285 34.330 ;
        RECT 15.605 34.205 20.415 34.330 ;
        RECT 15.605 30.115 15.965 34.205 ;
        RECT 16.275 30.425 19.745 33.895 ;
        RECT 20.055 30.115 20.415 34.205 ;
        RECT 15.605 29.970 20.415 30.115 ;
        RECT 20.735 29.970 21.725 34.330 ;
        RECT 22.045 34.205 26.855 34.330 ;
        RECT 22.045 30.115 22.405 34.205 ;
        RECT 22.715 30.425 26.185 33.895 ;
        RECT 26.495 30.115 26.855 34.205 ;
        RECT 22.045 29.970 26.855 30.115 ;
        RECT 27.175 29.970 28.165 34.330 ;
        RECT 28.485 34.205 33.295 34.330 ;
        RECT 28.485 30.115 28.845 34.205 ;
        RECT 29.155 30.425 32.625 33.895 ;
        RECT 32.935 30.115 33.295 34.205 ;
        RECT 28.485 29.970 33.295 30.115 ;
        RECT 33.615 29.970 34.605 34.330 ;
        RECT 34.925 34.205 39.735 34.330 ;
        RECT 34.925 30.115 35.285 34.205 ;
        RECT 35.595 30.425 39.065 33.895 ;
        RECT 39.375 30.115 39.735 34.205 ;
        RECT 34.925 29.970 39.735 30.115 ;
        RECT 40.055 29.970 41.045 34.330 ;
        RECT 41.365 34.205 46.175 34.330 ;
        RECT 41.365 30.115 41.725 34.205 ;
        RECT 42.035 30.425 45.505 33.895 ;
        RECT 45.815 30.115 46.175 34.205 ;
        RECT 41.365 29.970 46.175 30.115 ;
        RECT 46.495 29.970 46.990 34.330 ;
        RECT 14.790 27.950 46.990 29.970 ;
        RECT 14.790 23.440 15.285 27.950 ;
        RECT 15.605 27.765 20.415 27.950 ;
        RECT 15.605 23.675 15.965 27.765 ;
        RECT 16.275 23.985 19.745 27.455 ;
        RECT 20.055 23.675 20.415 27.765 ;
        RECT 15.605 23.440 20.415 23.675 ;
        RECT 20.735 23.440 21.725 27.950 ;
        RECT 22.045 27.765 26.855 27.950 ;
        RECT 22.045 23.675 22.405 27.765 ;
        RECT 22.715 23.985 26.185 27.455 ;
        RECT 26.495 23.675 26.855 27.765 ;
        RECT 22.045 23.440 26.855 23.675 ;
        RECT 27.175 23.440 28.165 27.950 ;
        RECT 28.485 27.765 33.295 27.950 ;
        RECT 28.485 23.675 28.845 27.765 ;
        RECT 29.155 23.985 32.625 27.455 ;
        RECT 32.935 23.675 33.295 27.765 ;
        RECT 28.485 23.440 33.295 23.675 ;
        RECT 33.615 23.440 34.605 27.950 ;
        RECT 34.925 27.765 39.735 27.950 ;
        RECT 34.925 23.675 35.285 27.765 ;
        RECT 35.595 23.985 39.065 27.455 ;
        RECT 39.375 23.675 39.735 27.765 ;
        RECT 34.925 23.440 39.735 23.675 ;
        RECT 40.055 23.440 41.045 27.950 ;
        RECT 41.365 27.765 46.175 27.950 ;
        RECT 41.365 23.675 41.725 27.765 ;
        RECT 42.035 23.985 45.505 27.455 ;
        RECT 45.815 23.675 46.175 27.765 ;
        RECT 41.365 23.440 46.175 23.675 ;
        RECT 46.495 23.440 46.990 27.950 ;
        RECT 48.120 26.010 48.680 40.770 ;
        RECT 49.860 39.970 51.300 41.170 ;
        RECT 50.940 36.370 51.300 39.970 ;
        RECT 52.020 39.970 53.460 41.170 ;
        RECT 52.020 36.370 52.380 39.970 ;
        RECT 50.940 26.770 52.380 29.170 ;
        RECT 54.640 26.010 55.200 41.930 ;
        RECT 48.120 25.450 55.200 26.010 ;
        RECT 55.910 26.960 56.470 42.880 ;
        RECT 57.650 40.920 59.090 42.120 ;
        RECT 58.730 37.320 59.090 40.920 ;
        RECT 59.810 40.920 61.250 42.120 ;
        RECT 59.810 37.320 60.170 40.920 ;
        RECT 60.890 37.320 61.250 40.920 ;
        RECT 61.970 40.920 63.410 42.120 ;
        RECT 61.970 37.320 62.330 40.920 ;
        RECT 63.050 37.320 63.410 40.920 ;
        RECT 64.130 40.920 65.570 42.120 ;
        RECT 64.130 37.320 64.490 40.920 ;
        RECT 65.210 37.320 65.570 40.920 ;
        RECT 66.290 40.920 67.730 42.120 ;
        RECT 66.290 37.320 66.650 40.920 ;
        RECT 67.370 37.320 67.730 40.920 ;
        RECT 68.450 40.920 69.890 42.120 ;
        RECT 68.450 37.320 68.810 40.920 ;
        RECT 69.530 37.320 69.890 40.920 ;
        RECT 70.610 40.920 72.050 42.120 ;
        RECT 70.610 37.320 70.970 40.920 ;
        RECT 71.690 37.320 72.050 40.920 ;
        RECT 72.770 40.920 74.210 42.120 ;
        RECT 72.770 37.320 73.130 40.920 ;
        RECT 73.850 37.320 74.210 40.920 ;
        RECT 74.930 40.920 76.370 42.120 ;
        RECT 74.930 37.320 75.290 40.920 ;
        RECT 58.730 27.720 60.170 30.120 ;
        RECT 60.890 27.720 62.330 30.120 ;
        RECT 63.050 27.720 64.490 30.120 ;
        RECT 65.210 27.720 66.650 30.120 ;
        RECT 67.370 27.720 68.810 30.120 ;
        RECT 69.530 27.720 70.970 30.120 ;
        RECT 71.690 27.720 73.130 30.120 ;
        RECT 73.850 27.720 75.290 30.120 ;
        RECT 77.550 26.960 78.110 42.880 ;
        RECT 82.030 35.015 120.320 35.090 ;
        RECT 82.030 34.130 138.635 35.015 ;
        RECT 82.030 32.660 82.990 34.130 ;
        RECT 83.950 33.350 86.190 33.750 ;
        RECT 80.670 30.450 82.990 32.660 ;
        RECT 83.310 31.350 83.630 32.550 ;
        RECT 84.590 31.750 86.830 32.150 ;
        RECT 87.150 31.350 87.470 32.550 ;
        RECT 80.670 30.320 81.630 30.450 ;
        RECT 55.910 26.400 78.110 26.960 ;
        RECT 82.030 29.930 82.990 30.450 ;
        RECT 83.950 30.150 86.190 30.550 ;
        RECT 87.790 29.930 89.490 34.130 ;
        RECT 90.450 33.350 92.690 33.750 ;
        RECT 89.810 31.350 90.130 32.550 ;
        RECT 91.090 31.750 93.330 32.150 ;
        RECT 93.650 31.350 93.970 32.550 ;
        RECT 90.450 30.150 92.690 30.550 ;
        RECT 94.290 29.930 95.990 34.130 ;
        RECT 96.950 32.550 100.470 32.950 ;
        RECT 96.310 31.350 96.630 32.550 ;
        RECT 97.590 31.750 101.110 32.150 ;
        RECT 101.430 31.350 101.750 32.550 ;
        RECT 96.950 30.950 100.470 31.350 ;
        RECT 102.070 29.930 103.990 34.130 ;
        RECT 104.950 32.550 108.470 32.950 ;
        RECT 104.310 31.350 104.630 32.550 ;
        RECT 105.590 31.750 109.110 32.150 ;
        RECT 109.430 31.350 109.750 32.550 ;
        RECT 104.950 30.950 108.470 31.350 ;
        RECT 110.070 29.930 111.990 34.130 ;
        RECT 112.950 32.550 116.470 32.950 ;
        RECT 112.310 31.350 112.630 32.550 ;
        RECT 113.590 31.750 117.110 32.150 ;
        RECT 117.430 31.350 117.750 32.550 ;
        RECT 112.950 30.950 116.470 31.350 ;
        RECT 118.070 29.930 119.030 34.130 ;
        RECT 119.965 33.920 138.635 34.130 ;
        RECT 82.030 29.095 121.305 29.930 ;
        RECT 14.790 21.420 46.990 23.440 ;
        RECT 14.790 16.990 15.285 21.420 ;
        RECT 15.605 21.325 20.415 21.420 ;
        RECT 15.605 17.235 15.965 21.325 ;
        RECT 16.275 17.545 19.745 21.015 ;
        RECT 20.055 17.235 20.415 21.325 ;
        RECT 15.605 16.990 20.415 17.235 ;
        RECT 20.735 16.990 21.725 21.420 ;
        RECT 22.045 21.325 26.855 21.420 ;
        RECT 22.045 17.235 22.405 21.325 ;
        RECT 22.715 17.545 26.185 21.015 ;
        RECT 26.495 17.235 26.855 21.325 ;
        RECT 22.045 16.990 26.855 17.235 ;
        RECT 27.175 16.990 28.165 21.420 ;
        RECT 28.485 21.325 33.295 21.420 ;
        RECT 28.485 17.235 28.845 21.325 ;
        RECT 29.155 17.545 32.625 21.015 ;
        RECT 32.935 17.235 33.295 21.325 ;
        RECT 28.485 16.990 33.295 17.235 ;
        RECT 33.615 16.990 34.605 21.420 ;
        RECT 34.925 21.325 39.735 21.420 ;
        RECT 34.925 17.235 35.285 21.325 ;
        RECT 35.595 17.545 39.065 21.015 ;
        RECT 39.375 17.235 39.735 21.325 ;
        RECT 34.925 16.990 39.735 17.235 ;
        RECT 40.055 16.990 41.045 21.420 ;
        RECT 41.365 21.325 46.175 21.420 ;
        RECT 41.365 17.235 41.725 21.325 ;
        RECT 42.035 17.545 45.505 21.015 ;
        RECT 45.815 17.235 46.175 21.325 ;
        RECT 41.365 16.990 46.175 17.235 ;
        RECT 46.495 16.990 46.990 21.420 ;
        RECT 14.790 14.970 46.990 16.990 ;
        RECT 14.790 10.115 15.285 14.970 ;
        RECT 15.605 14.885 20.415 14.970 ;
        RECT 15.605 10.795 15.965 14.885 ;
        RECT 16.275 11.105 19.745 14.575 ;
        RECT 20.055 10.795 20.415 14.885 ;
        RECT 15.605 10.435 20.415 10.795 ;
        RECT 20.735 10.115 21.725 14.970 ;
        RECT 22.045 14.885 26.855 14.970 ;
        RECT 22.045 10.795 22.405 14.885 ;
        RECT 22.715 11.105 26.185 14.575 ;
        RECT 26.495 10.795 26.855 14.885 ;
        RECT 22.045 10.435 26.855 10.795 ;
        RECT 27.175 10.115 28.165 14.970 ;
        RECT 28.485 14.885 33.295 14.970 ;
        RECT 28.485 10.795 28.845 14.885 ;
        RECT 29.155 11.105 32.625 14.575 ;
        RECT 32.935 10.795 33.295 14.885 ;
        RECT 28.485 10.435 33.295 10.795 ;
        RECT 33.615 10.115 34.605 14.970 ;
        RECT 34.925 14.885 39.735 14.970 ;
        RECT 34.925 10.795 35.285 14.885 ;
        RECT 35.595 11.105 39.065 14.575 ;
        RECT 39.375 10.795 39.735 14.885 ;
        RECT 34.925 10.435 39.735 10.795 ;
        RECT 40.055 10.115 41.045 14.970 ;
        RECT 41.365 14.885 46.175 14.970 ;
        RECT 41.365 10.795 41.725 14.885 ;
        RECT 42.035 11.105 45.505 14.575 ;
        RECT 45.815 10.795 46.175 14.885 ;
        RECT 41.365 10.435 46.175 10.795 ;
        RECT 46.495 10.115 46.990 14.970 ;
        RECT 14.790 9.620 46.990 10.115 ;
        RECT 55.910 25.390 65.150 26.400 ;
        RECT 72.380 25.620 73.340 25.660 ;
        RECT 55.910 9.470 56.470 25.390 ;
        RECT 57.650 23.430 59.090 24.630 ;
        RECT 58.730 19.830 59.090 23.430 ;
        RECT 59.810 23.430 61.250 24.630 ;
        RECT 59.810 19.830 60.170 23.430 ;
        RECT 60.890 19.830 61.250 23.430 ;
        RECT 61.970 23.430 63.410 24.630 ;
        RECT 61.970 19.830 62.330 23.430 ;
        RECT 58.730 10.230 60.170 12.630 ;
        RECT 60.890 10.230 62.330 12.630 ;
        RECT 64.590 11.590 65.150 25.390 ;
        RECT 65.870 21.290 66.830 25.620 ;
        RECT 67.790 24.820 70.030 25.220 ;
        RECT 67.150 22.820 67.470 24.020 ;
        RECT 68.430 23.220 70.670 23.620 ;
        RECT 70.990 22.820 71.310 24.020 ;
        RECT 67.790 21.620 70.030 22.020 ;
        RECT 71.630 21.840 73.340 25.620 ;
        RECT 74.300 24.860 76.540 25.260 ;
        RECT 73.660 22.860 73.980 24.060 ;
        RECT 74.940 23.260 77.180 23.660 ;
        RECT 77.500 22.860 77.820 24.060 ;
        RECT 71.600 21.290 73.340 21.840 ;
        RECT 74.300 21.660 76.540 22.060 ;
        RECT 78.140 21.290 79.100 25.660 ;
        RECT 82.030 24.915 82.990 29.095 ;
        RECT 83.950 28.350 86.190 28.750 ;
        RECT 83.310 26.350 83.630 27.550 ;
        RECT 84.590 26.750 86.830 27.150 ;
        RECT 87.150 26.350 87.470 27.550 ;
        RECT 83.950 25.150 86.190 25.550 ;
        RECT 87.790 24.915 89.490 29.095 ;
        RECT 90.450 28.350 92.690 28.750 ;
        RECT 89.810 26.350 90.130 27.550 ;
        RECT 91.090 26.750 93.330 27.150 ;
        RECT 93.650 26.350 93.970 27.550 ;
        RECT 90.450 25.150 92.690 25.550 ;
        RECT 94.290 24.915 95.990 29.095 ;
        RECT 96.950 28.350 99.190 28.750 ;
        RECT 96.310 26.350 96.630 27.550 ;
        RECT 97.590 26.750 99.830 27.150 ;
        RECT 100.150 26.350 100.470 27.550 ;
        RECT 96.950 25.150 99.190 25.550 ;
        RECT 100.790 24.915 102.490 29.095 ;
        RECT 103.450 28.350 105.690 28.750 ;
        RECT 102.810 26.350 103.130 27.550 ;
        RECT 104.090 26.750 106.330 27.150 ;
        RECT 106.650 26.350 106.970 27.550 ;
        RECT 103.450 25.150 105.690 25.550 ;
        RECT 107.290 24.915 108.990 29.095 ;
        RECT 109.950 28.350 112.190 28.750 ;
        RECT 109.310 26.350 109.630 27.550 ;
        RECT 110.590 26.750 112.830 27.150 ;
        RECT 113.150 26.350 113.470 27.550 ;
        RECT 109.950 25.150 112.190 25.550 ;
        RECT 113.790 24.915 115.490 29.095 ;
        RECT 116.450 28.350 118.690 28.750 ;
        RECT 115.810 26.350 116.130 27.550 ;
        RECT 117.090 26.750 119.330 27.150 ;
        RECT 119.650 26.350 119.970 27.550 ;
        RECT 116.450 25.150 118.690 25.550 ;
        RECT 120.290 24.915 121.250 29.095 ;
        RECT 122.790 24.915 123.750 25.190 ;
        RECT 81.990 24.510 123.750 24.915 ;
        RECT 81.990 23.110 114.790 23.610 ;
        RECT 65.870 20.850 79.120 21.290 ;
        RECT 65.840 20.830 79.120 20.850 ;
        RECT 65.840 20.070 66.830 20.830 ;
        RECT 65.840 16.490 66.800 20.070 ;
        RECT 67.760 20.050 70.000 20.450 ;
        RECT 67.120 18.050 67.440 19.250 ;
        RECT 68.400 18.450 70.640 18.850 ;
        RECT 70.960 18.050 71.280 19.250 ;
        RECT 67.760 16.850 70.000 17.250 ;
        RECT 71.600 16.490 73.340 20.830 ;
        RECT 74.300 20.050 76.540 20.450 ;
        RECT 73.660 18.050 73.980 19.250 ;
        RECT 74.940 18.450 77.180 18.850 ;
        RECT 77.500 18.050 77.820 19.250 ;
        RECT 74.300 16.850 76.540 17.250 ;
        RECT 78.140 16.490 79.100 20.830 ;
        RECT 65.820 15.690 80.830 16.490 ;
        RECT 65.820 15.530 80.860 15.690 ;
        RECT 65.820 11.590 66.780 15.530 ;
        RECT 67.740 14.090 71.260 14.490 ;
        RECT 67.100 12.890 67.420 14.090 ;
        RECT 68.380 13.290 71.900 13.690 ;
        RECT 72.220 12.890 72.540 14.090 ;
        RECT 67.740 12.490 71.260 12.890 ;
        RECT 72.860 11.590 73.820 15.530 ;
        RECT 74.780 14.090 78.300 14.490 ;
        RECT 74.140 12.890 74.460 14.090 ;
        RECT 75.420 13.290 78.940 13.690 ;
        RECT 79.260 12.890 79.580 14.090 ;
        RECT 74.780 12.490 78.300 12.890 ;
        RECT 79.900 11.590 80.860 15.530 ;
        RECT 82.030 14.910 82.990 23.110 ;
        RECT 83.950 22.350 86.190 22.750 ;
        RECT 83.310 20.350 83.630 21.550 ;
        RECT 84.590 20.750 86.830 21.150 ;
        RECT 87.150 20.350 87.470 21.550 ;
        RECT 83.950 19.150 86.190 19.550 ;
        RECT 83.950 18.350 86.190 18.750 ;
        RECT 83.310 16.350 83.630 17.550 ;
        RECT 84.590 16.750 86.830 17.150 ;
        RECT 87.150 16.350 87.470 17.550 ;
        RECT 83.950 15.150 86.190 15.550 ;
        RECT 87.790 14.910 89.490 23.110 ;
        RECT 90.450 22.350 92.690 22.750 ;
        RECT 89.810 20.350 90.130 21.550 ;
        RECT 91.090 20.750 93.330 21.150 ;
        RECT 93.650 20.350 93.970 21.550 ;
        RECT 90.450 19.150 92.690 19.550 ;
        RECT 90.450 18.350 92.690 18.750 ;
        RECT 89.810 16.350 90.130 17.550 ;
        RECT 91.090 16.750 93.330 17.150 ;
        RECT 93.650 16.350 93.970 17.550 ;
        RECT 90.450 15.150 92.690 15.550 ;
        RECT 94.290 14.910 95.990 23.110 ;
        RECT 96.950 22.350 99.190 22.750 ;
        RECT 96.310 20.350 96.630 21.550 ;
        RECT 97.590 20.750 99.830 21.150 ;
        RECT 100.150 20.350 100.470 21.550 ;
        RECT 96.950 19.150 99.190 19.550 ;
        RECT 96.950 18.350 99.190 18.750 ;
        RECT 96.310 16.350 96.630 17.550 ;
        RECT 97.590 16.750 99.830 17.150 ;
        RECT 100.150 16.350 100.470 17.550 ;
        RECT 96.950 15.150 99.190 15.550 ;
        RECT 100.790 14.910 102.490 23.110 ;
        RECT 103.450 22.350 105.690 22.750 ;
        RECT 102.810 20.350 103.130 21.550 ;
        RECT 104.090 20.750 106.330 21.150 ;
        RECT 106.650 20.350 106.970 21.550 ;
        RECT 103.450 19.150 105.690 19.550 ;
        RECT 103.450 18.350 105.690 18.750 ;
        RECT 102.810 16.350 103.130 17.550 ;
        RECT 104.090 16.750 106.330 17.150 ;
        RECT 106.650 16.350 106.970 17.550 ;
        RECT 103.450 15.150 105.690 15.550 ;
        RECT 107.290 14.910 108.990 23.110 ;
        RECT 109.950 22.350 112.190 22.750 ;
        RECT 109.310 20.350 109.630 21.550 ;
        RECT 110.590 20.750 112.830 21.150 ;
        RECT 113.150 20.350 113.470 21.550 ;
        RECT 109.950 19.150 112.190 19.550 ;
        RECT 109.950 18.350 112.190 18.750 ;
        RECT 109.310 16.350 109.630 17.550 ;
        RECT 110.590 16.750 112.830 17.150 ;
        RECT 113.150 16.350 113.470 17.550 ;
        RECT 109.950 15.150 112.190 15.550 ;
        RECT 113.790 14.910 114.750 23.110 ;
        RECT 82.030 14.115 114.785 14.910 ;
        RECT 82.030 11.590 82.990 14.115 ;
        RECT 83.950 12.550 87.470 12.950 ;
        RECT 64.590 10.630 82.990 11.590 ;
        RECT 83.310 11.350 83.630 12.550 ;
        RECT 84.590 11.750 88.110 12.150 ;
        RECT 88.430 11.350 88.750 12.550 ;
        RECT 83.950 10.950 87.470 11.350 ;
        RECT 64.590 9.470 65.150 10.630 ;
        RECT 67.830 10.620 68.610 10.630 ;
        RECT 74.870 10.620 75.650 10.630 ;
        RECT 47.710 8.910 65.150 9.470 ;
        RECT 82.030 9.890 82.990 10.630 ;
        RECT 89.070 9.890 90.990 14.115 ;
        RECT 91.950 12.550 95.470 12.950 ;
        RECT 91.310 11.350 91.630 12.550 ;
        RECT 92.590 11.750 96.110 12.150 ;
        RECT 96.430 11.350 96.750 12.550 ;
        RECT 91.950 10.950 95.470 11.350 ;
        RECT 97.070 9.890 98.990 14.115 ;
        RECT 99.950 12.550 103.470 12.950 ;
        RECT 99.310 11.350 99.630 12.550 ;
        RECT 100.590 11.750 104.110 12.150 ;
        RECT 104.430 11.350 104.750 12.550 ;
        RECT 99.950 10.950 103.470 11.350 ;
        RECT 105.070 9.890 106.990 14.115 ;
        RECT 107.950 13.350 110.190 13.750 ;
        RECT 107.310 11.350 107.630 12.550 ;
        RECT 108.590 11.750 110.830 12.150 ;
        RECT 111.150 11.350 111.470 12.550 ;
        RECT 107.950 10.150 110.190 10.550 ;
        RECT 111.790 9.890 112.750 14.115 ;
        RECT 117.030 12.290 117.990 24.510 ;
        RECT 118.950 23.850 121.190 24.250 ;
        RECT 118.310 21.850 118.630 23.050 ;
        RECT 119.590 22.250 121.830 22.650 ;
        RECT 122.150 21.850 122.470 23.050 ;
        RECT 118.950 20.650 121.190 21.050 ;
        RECT 118.950 19.850 121.190 20.250 ;
        RECT 118.310 17.850 118.630 19.050 ;
        RECT 119.590 18.250 121.830 18.650 ;
        RECT 122.150 17.850 122.470 19.050 ;
        RECT 118.950 16.650 121.190 17.050 ;
        RECT 118.950 15.850 121.190 16.250 ;
        RECT 118.310 13.850 118.630 15.050 ;
        RECT 119.590 14.250 121.830 14.650 ;
        RECT 122.150 13.850 122.470 15.050 ;
        RECT 118.950 12.650 121.190 13.050 ;
        RECT 122.790 12.290 123.750 24.510 ;
        RECT 128.940 13.070 129.840 31.520 ;
        RECT 135.240 31.070 136.080 31.090 ;
        RECT 132.540 30.770 136.140 31.070 ;
        RECT 130.740 30.370 132.240 30.670 ;
        RECT 137.040 30.370 137.940 30.670 ;
        RECT 131.940 29.470 132.240 30.370 ;
        RECT 132.540 30.270 133.380 30.290 ;
        RECT 135.240 30.270 136.080 30.290 ;
        RECT 132.540 29.970 133.440 30.270 ;
        RECT 135.240 29.970 136.140 30.270 ;
        RECT 132.540 29.470 133.380 29.490 ;
        RECT 131.940 29.170 136.140 29.470 ;
        RECT 130.740 29.070 131.580 29.090 ;
        RECT 130.740 28.770 131.640 29.070 ;
        RECT 136.440 28.770 137.940 29.070 ;
        RECT 132.540 28.370 136.140 28.670 ;
        RECT 130.740 27.970 131.640 28.270 ;
        RECT 132.540 27.570 133.440 27.870 ;
        RECT 130.110 27.470 130.410 27.500 ;
        RECT 130.740 27.470 131.580 27.490 ;
        RECT 130.110 27.170 131.640 27.470 ;
        RECT 130.110 26.600 130.410 27.170 ;
        RECT 132.540 27.070 133.380 27.090 ;
        RECT 134.640 27.070 134.940 28.370 ;
        RECT 135.240 27.870 136.080 27.890 ;
        RECT 135.240 27.570 136.140 27.870 ;
        RECT 132.540 26.770 133.440 27.070 ;
        RECT 134.640 26.770 136.140 27.070 ;
        RECT 132.540 26.270 133.380 26.290 ;
        RECT 132.540 25.970 136.140 26.270 ;
        RECT 130.740 25.570 131.640 25.870 ;
        RECT 131.340 25.270 132.240 25.570 ;
        RECT 130.740 24.770 131.640 25.070 ;
        RECT 130.740 23.470 131.580 23.490 ;
        RECT 130.740 23.170 131.640 23.470 ;
        RECT 131.940 21.870 132.240 25.270 ;
        RECT 132.540 25.170 133.440 25.470 ;
        RECT 135.240 25.170 136.140 25.470 ;
        RECT 132.540 24.670 133.380 24.690 ;
        RECT 135.240 24.670 136.080 24.690 ;
        RECT 132.540 24.370 133.440 24.670 ;
        RECT 135.240 24.370 136.140 24.670 ;
        RECT 135.240 23.870 136.080 23.890 ;
        RECT 132.540 23.570 136.140 23.870 ;
        RECT 132.540 23.070 133.380 23.090 ;
        RECT 135.240 23.070 136.080 23.090 ;
        RECT 132.540 22.770 133.440 23.070 ;
        RECT 135.240 22.770 136.140 23.070 ;
        RECT 132.540 22.270 133.380 22.290 ;
        RECT 132.540 21.970 136.140 22.270 ;
        RECT 130.740 21.570 132.240 21.870 ;
        RECT 130.740 20.770 131.640 21.070 ;
        RECT 130.740 19.470 131.580 19.490 ;
        RECT 130.740 19.170 131.640 19.470 ;
        RECT 130.740 18.370 131.640 18.670 ;
        RECT 131.940 17.470 132.240 21.570 ;
        RECT 132.540 21.170 133.440 21.470 ;
        RECT 132.540 20.670 133.380 20.690 ;
        RECT 132.540 20.370 133.440 20.670 ;
        RECT 133.740 19.870 134.040 21.970 ;
        RECT 135.240 21.170 136.140 21.470 ;
        RECT 135.240 20.670 136.080 20.690 ;
        RECT 135.240 20.370 136.140 20.670 ;
        RECT 132.540 19.570 136.140 19.870 ;
        RECT 136.440 19.470 136.740 28.770 ;
        RECT 137.040 28.270 137.880 28.290 ;
        RECT 137.040 27.970 137.940 28.270 ;
        RECT 137.040 27.170 137.940 27.470 ;
        RECT 137.040 25.870 137.880 25.890 ;
        RECT 137.040 25.570 137.940 25.870 ;
        RECT 137.040 25.070 137.880 25.090 ;
        RECT 137.040 24.770 137.940 25.070 ;
        RECT 137.040 23.170 137.940 23.470 ;
        RECT 137.040 21.870 137.880 21.890 ;
        RECT 137.040 21.570 137.940 21.870 ;
        RECT 137.040 21.070 137.880 21.090 ;
        RECT 137.040 20.770 137.940 21.070 ;
        RECT 136.440 19.170 137.940 19.470 ;
        RECT 132.540 18.770 133.440 19.070 ;
        RECT 135.240 18.770 136.140 19.070 ;
        RECT 132.540 18.270 133.380 18.290 ;
        RECT 135.240 18.270 136.080 18.290 ;
        RECT 132.540 17.970 133.440 18.270 ;
        RECT 135.240 17.970 136.140 18.270 ;
        RECT 136.440 17.470 136.740 19.170 ;
        RECT 137.040 18.370 137.940 18.670 ;
        RECT 131.940 17.170 136.740 17.470 ;
        RECT 130.740 16.770 131.640 17.070 ;
        RECT 137.040 16.770 137.940 17.070 ;
        RECT 132.540 16.670 133.380 16.690 ;
        RECT 135.240 16.670 136.080 16.690 ;
        RECT 132.540 16.370 133.440 16.670 ;
        RECT 135.240 16.370 136.140 16.670 ;
        RECT 136.440 16.470 137.340 16.770 ;
        RECT 132.540 15.870 133.380 15.890 ;
        RECT 135.240 15.870 136.080 15.890 ;
        RECT 132.540 15.570 134.040 15.870 ;
        RECT 135.240 15.570 136.140 15.870 ;
        RECT 130.740 15.470 131.580 15.490 ;
        RECT 130.740 15.170 131.640 15.470 ;
        RECT 133.740 15.070 134.040 15.570 ;
        RECT 135.240 15.070 136.080 15.090 ;
        RECT 136.440 15.070 136.740 16.470 ;
        RECT 137.040 15.170 137.940 15.470 ;
        RECT 132.540 14.770 133.440 15.070 ;
        RECT 133.740 14.770 136.740 15.070 ;
        RECT 130.740 14.370 131.640 14.670 ;
        RECT 137.040 14.370 137.940 14.670 ;
        RECT 132.540 14.270 133.380 14.290 ;
        RECT 135.240 14.270 136.080 14.290 ;
        RECT 132.540 13.970 133.440 14.270 ;
        RECT 135.240 13.970 136.140 14.270 ;
        RECT 132.540 13.470 133.380 13.490 ;
        RECT 135.240 13.470 136.080 13.490 ;
        RECT 131.940 13.170 133.440 13.470 ;
        RECT 135.240 13.170 136.740 13.470 ;
        RECT 131.940 13.070 132.240 13.170 ;
        RECT 128.940 12.770 132.240 13.070 ;
        RECT 117.030 11.330 123.770 12.290 ;
        RECT 128.940 11.920 129.840 12.770 ;
        RECT 131.940 12.670 132.240 12.770 ;
        RECT 136.440 13.070 136.740 13.170 ;
        RECT 138.840 13.070 139.740 31.520 ;
        RECT 136.440 12.770 139.740 13.070 ;
        RECT 132.540 12.670 133.380 12.690 ;
        RECT 135.240 12.670 136.080 12.690 ;
        RECT 136.440 12.670 136.740 12.770 ;
        RECT 131.940 12.370 133.440 12.670 ;
        RECT 135.240 12.370 136.740 12.670 ;
        RECT 138.840 11.920 139.740 12.770 ;
        RECT 82.030 9.785 112.870 9.890 ;
        RECT 82.030 8.940 128.970 9.785 ;
        RECT 82.030 8.930 112.870 8.940 ;
        RECT 84.040 8.920 84.820 8.930 ;
        RECT 126.630 8.870 128.800 8.940 ;
      LAYER met1 ;
        RECT 136.230 109.025 136.910 109.080 ;
        RECT 136.225 108.970 136.910 109.025 ;
        RECT 136.225 108.670 137.950 108.970 ;
        RECT 136.225 108.635 136.910 108.670 ;
        RECT 136.230 108.600 136.910 108.635 ;
        RECT 137.650 108.150 137.950 108.670 ;
        RECT 141.570 107.680 141.870 107.710 ;
        RECT 141.570 107.380 142.430 107.680 ;
        RECT 141.570 107.350 141.870 107.380 ;
        RECT 142.580 106.080 143.460 106.420 ;
        RECT 145.280 106.080 146.160 106.420 ;
        RECT 142.580 105.280 143.460 105.620 ;
        RECT 145.280 105.280 146.160 105.620 ;
        RECT 142.580 104.480 143.460 104.820 ;
        RECT 145.280 104.480 146.160 104.820 ;
        RECT 45.300 93.900 46.260 95.110 ;
        RECT 52.870 94.230 53.890 95.190 ;
        RECT 45.270 92.940 46.290 93.900 ;
        RECT 9.040 91.940 10.000 91.990 ;
        RECT 6.430 91.930 10.000 91.940 ;
        RECT 10.400 91.930 11.360 91.990 ;
        RECT 6.410 90.970 11.360 91.930 ;
        RECT 6.430 90.960 10.000 90.970 ;
        RECT 9.040 90.910 10.000 90.960 ;
        RECT 10.400 90.910 11.360 90.970 ;
        RECT 25.475 90.035 25.805 90.065 ;
        RECT 24.775 89.705 26.435 90.035 ;
        RECT 24.775 85.035 25.105 89.705 ;
        RECT 25.475 89.675 25.805 89.705 ;
        RECT 29.830 89.490 31.820 90.450 ;
        RECT 30.860 87.550 31.820 89.490 ;
        RECT 34.280 89.610 36.130 89.930 ;
        RECT 30.830 86.590 31.850 87.550 ;
        RECT 24.745 84.705 25.135 85.035 ;
        RECT 24.775 84.335 25.105 84.705 ;
        RECT 24.745 84.005 25.135 84.335 ;
        RECT 34.280 82.630 34.600 89.610 ;
        RECT 39.630 89.490 41.520 90.450 ;
        RECT 40.560 87.650 41.520 89.490 ;
        RECT 44.660 87.840 44.980 91.010 ;
        RECT 40.530 86.690 41.550 87.650 ;
        RECT 42.920 87.500 43.900 87.820 ;
        RECT 44.630 87.520 45.010 87.840 ;
        RECT 42.950 82.910 43.270 87.500 ;
        RECT 44.660 87.410 44.980 87.520 ;
        RECT 45.300 87.410 46.260 92.940 ;
        RECT 47.140 90.770 47.540 90.800 ;
        RECT 47.740 90.770 48.140 90.800 ;
        RECT 48.500 90.770 49.460 91.010 ;
        RECT 47.140 90.370 49.460 90.770 ;
        RECT 47.140 90.340 47.540 90.370 ;
        RECT 47.740 90.340 48.140 90.370 ;
        RECT 48.500 87.150 49.460 90.370 ;
        RECT 52.260 88.470 52.580 91.010 ;
        RECT 52.250 88.150 52.630 88.470 ;
        RECT 52.260 87.410 52.580 88.150 ;
        RECT 52.900 87.410 53.860 94.230 ;
        RECT 60.560 94.000 61.400 95.050 ;
        RECT 60.530 93.160 61.430 94.000 ;
        RECT 60.560 91.010 61.400 93.160 ;
        RECT 65.400 92.140 66.280 92.170 ;
        RECT 67.170 92.140 68.050 92.170 ;
        RECT 68.400 92.140 69.280 92.170 ;
        RECT 64.140 91.260 69.280 92.140 ;
        RECT 65.400 91.230 66.280 91.260 ;
        RECT 67.170 91.230 68.050 91.260 ;
        RECT 68.400 91.230 69.280 91.260 ;
        RECT 56.100 87.250 57.060 91.010 ;
        RECT 59.860 88.400 60.180 91.010 ;
        RECT 59.850 88.080 60.230 88.400 ;
        RECT 59.860 87.870 60.180 88.080 ;
        RECT 59.860 87.490 60.220 87.870 ;
        RECT 59.860 87.410 60.180 87.490 ;
        RECT 60.500 87.410 61.460 91.010 ;
        RECT 50.960 87.150 57.060 87.250 ;
        RECT 63.700 87.150 64.660 91.010 ;
        RECT 45.260 86.290 64.660 87.150 ;
        RECT 68.640 87.120 68.940 87.910 ;
        RECT 68.610 86.820 68.970 87.120 ;
        RECT 45.260 86.190 51.920 86.290 ;
        RECT 45.260 85.910 46.220 86.190 ;
        RECT 50.960 85.910 51.920 86.190 ;
        RECT 56.760 86.190 64.660 86.290 ;
        RECT 56.760 85.910 57.720 86.190 ;
        RECT 34.250 82.310 34.630 82.630 ;
        RECT 42.920 82.590 43.300 82.910 ;
        RECT 42.950 82.330 43.270 82.590 ;
        RECT 34.280 82.030 34.600 82.310 ;
        RECT 34.250 81.710 34.630 82.030 ;
        RECT 42.920 82.010 43.300 82.330 ;
        RECT 44.660 77.730 44.980 85.910 ;
        RECT 45.260 85.390 46.260 85.910 ;
        RECT 45.300 82.310 46.260 85.390 ;
        RECT 46.580 82.310 47.540 85.910 ;
        RECT 45.300 81.280 46.260 81.710 ;
        RECT 45.260 80.260 46.260 81.280 ;
        RECT 45.300 78.110 46.260 80.260 ;
        RECT 46.580 81.240 47.540 81.710 ;
        RECT 46.580 80.220 47.570 81.240 ;
        RECT 46.580 78.110 47.540 80.220 ;
        RECT 50.360 78.330 50.680 85.910 ;
        RECT 50.960 85.190 51.960 85.910 ;
        RECT 51.000 82.310 51.960 85.190 ;
        RECT 52.280 82.310 53.240 85.910 ;
        RECT 51.000 81.180 51.960 81.710 ;
        RECT 50.960 80.160 51.960 81.180 ;
        RECT 50.360 78.110 50.700 78.330 ;
        RECT 51.000 78.110 51.960 80.160 ;
        RECT 52.280 79.550 53.240 81.710 ;
        RECT 52.250 78.590 53.270 79.550 ;
        RECT 52.280 78.110 53.240 78.590 ;
        RECT 56.060 78.130 56.380 85.910 ;
        RECT 56.700 85.490 57.720 85.910 ;
        RECT 56.700 82.310 57.660 85.490 ;
        RECT 57.980 82.310 58.940 85.910 ;
        RECT 62.660 85.810 63.620 86.190 ;
        RECT 68.640 86.140 68.940 86.820 ;
        RECT 68.630 86.110 68.950 86.140 ;
        RECT 62.060 83.030 62.380 85.810 ;
        RECT 62.660 85.190 63.660 85.810 ;
        RECT 62.030 82.710 62.410 83.030 ;
        RECT 62.060 82.530 62.380 82.710 ;
        RECT 62.050 82.210 62.430 82.530 ;
        RECT 56.700 81.250 57.660 81.710 ;
        RECT 56.630 80.290 57.660 81.250 ;
        RECT 56.060 78.110 56.400 78.130 ;
        RECT 56.700 78.110 57.660 80.290 ;
        RECT 57.980 79.650 58.940 81.710 ;
        RECT 57.950 78.690 58.970 79.650 ;
        RECT 57.980 78.110 58.940 78.690 ;
        RECT 62.060 78.210 62.380 82.210 ;
        RECT 62.700 78.210 63.660 85.190 ;
        RECT 64.620 83.150 65.580 85.810 ;
        RECT 68.600 85.790 68.980 86.110 ;
        RECT 68.630 85.760 68.950 85.790 ;
        RECT 70.080 85.770 71.020 86.680 ;
        RECT 68.640 83.970 68.940 85.760 ;
        RECT 68.550 83.670 68.970 83.970 ;
        RECT 68.640 83.290 68.940 83.670 ;
        RECT 64.620 82.210 67.180 83.150 ;
        RECT 68.580 82.990 69.000 83.290 ;
        RECT 64.660 82.190 67.180 82.210 ;
        RECT 64.620 78.530 65.580 81.810 ;
        RECT 64.620 78.210 65.600 78.530 ;
        RECT 50.380 77.730 50.700 78.110 ;
        RECT 56.080 77.730 56.400 78.110 ;
        RECT 44.660 77.495 56.400 77.730 ;
        RECT 44.615 77.410 56.400 77.495 ;
        RECT 44.615 76.840 53.240 77.410 ;
        RECT 26.000 74.775 31.500 75.095 ;
        RECT 26.000 73.325 26.320 74.775 ;
        RECT 26.605 73.325 27.555 74.410 ;
        RECT 31.180 73.690 31.500 74.775 ;
        RECT 31.150 73.370 31.530 73.690 ;
        RECT 25.930 72.975 26.320 73.325 ;
        RECT 25.960 72.700 26.280 72.975 ;
        RECT 25.930 72.380 26.310 72.700 ;
        RECT 25.960 69.725 26.280 72.380 ;
        RECT 26.600 69.725 27.560 73.325 ;
        RECT 29.800 70.365 30.760 73.325 ;
        RECT 31.180 72.825 31.500 73.370 ;
        RECT 33.960 73.205 34.280 73.325 ;
        RECT 33.940 73.175 34.280 73.205 ;
        RECT 33.910 72.855 34.290 73.175 ;
        RECT 33.940 72.825 34.280 72.855 ;
        RECT 33.960 72.610 34.280 72.825 ;
        RECT 33.935 72.230 34.280 72.610 ;
        RECT 29.770 69.405 30.790 70.365 ;
        RECT 33.960 69.725 34.280 72.230 ;
        RECT 34.600 69.725 35.560 74.385 ;
        RECT 42.615 73.325 43.550 74.425 ;
        RECT 37.800 70.405 38.760 73.325 ;
        RECT 41.960 73.175 42.280 73.325 ;
        RECT 41.930 72.855 42.310 73.175 ;
        RECT 41.960 72.600 42.280 72.855 ;
        RECT 41.935 72.280 42.315 72.600 ;
        RECT 29.800 69.225 30.760 69.405 ;
        RECT 37.750 69.335 38.760 70.405 ;
        RECT 41.960 69.725 42.280 72.280 ;
        RECT 42.600 69.725 43.560 73.325 ;
        RECT 45.800 70.395 46.760 73.325 ;
        RECT 45.100 69.225 46.760 70.395 ;
        RECT 48.815 70.295 49.470 76.840 ;
        RECT 51.040 76.330 53.240 76.840 ;
        RECT 65.280 76.330 65.600 78.210 ;
        RECT 51.040 76.010 65.600 76.330 ;
        RECT 51.060 71.610 51.380 76.010 ;
        RECT 54.280 75.210 54.600 76.010 ;
        RECT 51.700 70.360 52.660 75.210 ;
        RECT 53.620 74.810 54.600 75.210 ;
        RECT 57.360 75.510 60.900 75.830 ;
        RECT 53.620 71.610 54.580 74.810 ;
        RECT 57.360 71.610 57.680 75.510 ;
        RECT 60.580 75.210 60.900 75.510 ;
        RECT 63.680 75.210 64.000 76.010 ;
        RECT 58.000 70.360 58.960 75.210 ;
        RECT 59.920 74.810 60.900 75.210 ;
        RECT 59.920 72.050 60.880 74.810 ;
        RECT 63.660 74.710 64.000 75.210 ;
        RECT 59.920 71.610 60.920 72.050 ;
        RECT 63.660 71.610 63.980 74.710 ;
        RECT 59.960 70.950 60.920 71.610 ;
        RECT 64.300 70.950 65.260 75.210 ;
        RECT 66.220 71.610 67.180 82.190 ;
        RECT 68.200 75.660 69.080 75.690 ;
        RECT 70.110 75.660 70.990 85.770 ;
        RECT 88.950 85.680 89.350 85.710 ;
        RECT 87.850 85.280 89.380 85.680 ;
        RECT 79.770 85.030 80.170 85.060 ;
        RECT 79.100 84.630 80.170 85.030 ;
        RECT 79.130 79.990 79.530 84.630 ;
        RECT 79.770 84.600 80.170 84.630 ;
        RECT 88.950 84.610 89.350 85.280 ;
        RECT 88.890 84.210 89.410 84.610 ;
        RECT 88.950 83.670 89.350 84.210 ;
        RECT 88.890 83.270 89.410 83.670 ;
        RECT 80.410 82.270 89.120 82.670 ;
        RECT 80.710 81.770 81.130 81.790 ;
        RECT 80.710 81.490 81.580 81.770 ;
        RECT 80.770 81.470 81.580 81.490 ;
        RECT 80.770 80.100 81.070 81.470 ;
        RECT 82.500 81.120 83.380 81.460 ;
        RECT 85.200 81.120 86.080 81.460 ;
        RECT 99.440 80.190 99.740 80.220 ;
        RECT 98.120 80.100 99.740 80.190 ;
        RECT 79.100 79.590 79.560 79.990 ;
        RECT 80.770 79.860 99.740 80.100 ;
        RECT 80.770 79.800 99.690 79.860 ;
        RECT 79.130 79.260 79.530 79.590 ;
        RECT 79.070 78.860 79.590 79.260 ;
        RECT 82.480 75.770 83.360 76.110 ;
        RECT 85.180 75.770 86.060 76.110 ;
        RECT 68.170 74.780 70.990 75.660 ;
        RECT 68.200 73.520 69.080 74.780 ;
        RECT 83.870 74.210 84.170 74.920 ;
        RECT 83.840 74.200 84.170 74.210 ;
        RECT 70.905 73.635 84.200 74.200 ;
        RECT 48.815 69.640 50.840 70.295 ;
        RECT 59.960 69.990 65.260 70.950 ;
        RECT 31.465 68.325 31.785 68.335 ;
        RECT 24.960 67.025 26.560 68.325 ;
        RECT 24.960 66.025 25.280 67.025 ;
        RECT 25.600 66.025 26.560 67.025 ;
        RECT 24.960 64.725 26.560 66.025 ;
        RECT 25.600 64.325 26.560 64.725 ;
        RECT 27.520 64.325 28.480 68.325 ;
        RECT 31.460 68.025 31.785 68.325 ;
        RECT 31.435 67.705 31.815 68.025 ;
        RECT 32.100 67.830 33.060 68.325 ;
        RECT 31.460 67.500 31.785 67.705 ;
        RECT 31.445 67.200 31.805 67.500 ;
        RECT 31.460 66.360 31.785 67.200 ;
        RECT 32.100 66.810 33.065 67.830 ;
        RECT 31.460 64.725 31.780 66.360 ;
        RECT 24.960 63.025 28.480 64.325 ;
        RECT 31.460 64.240 31.780 64.325 ;
        RECT 31.425 63.920 31.805 64.240 ;
        RECT 31.460 63.730 31.780 63.920 ;
        RECT 31.455 63.350 31.780 63.730 ;
        RECT 24.960 62.025 25.280 63.025 ;
        RECT 25.600 62.025 26.560 63.025 ;
        RECT 27.520 62.025 28.480 63.025 ;
        RECT 24.960 60.725 28.480 62.025 ;
        RECT 31.460 61.075 31.780 63.350 ;
        RECT 31.430 60.755 31.810 61.075 ;
        RECT 31.460 60.725 31.780 60.755 ;
        RECT 25.600 60.325 26.560 60.725 ;
        RECT 27.520 60.325 28.480 60.725 ;
        RECT 14.305 59.860 14.805 59.890 ;
        RECT 15.005 59.860 15.505 59.890 ;
        RECT 13.680 59.360 15.505 59.860 ;
        RECT 13.680 59.155 14.145 59.360 ;
        RECT 14.305 59.330 14.805 59.360 ;
        RECT 15.005 59.330 15.505 59.360 ;
        RECT 13.680 59.150 14.180 59.155 ;
        RECT 13.680 58.650 15.575 59.150 ;
        RECT 24.960 59.025 28.480 60.325 ;
        RECT 31.460 60.270 31.780 60.325 ;
        RECT 31.425 59.950 31.805 60.270 ;
        RECT 31.460 59.690 31.780 59.950 ;
        RECT 31.455 59.310 31.780 59.690 ;
        RECT 18.720 58.410 22.345 58.850 ;
        RECT 21.905 56.115 22.345 58.410 ;
        RECT 24.960 58.025 25.280 59.025 ;
        RECT 25.600 58.025 26.560 59.025 ;
        RECT 27.520 58.025 28.480 59.025 ;
        RECT 24.960 56.725 28.480 58.025 ;
        RECT 31.460 56.725 31.780 59.310 ;
        RECT 32.100 56.725 33.060 66.810 ;
        RECT 34.020 66.180 34.980 68.325 ;
        RECT 37.960 68.235 38.280 68.325 ;
        RECT 37.930 67.915 38.310 68.235 ;
        RECT 37.960 67.685 38.280 67.915 ;
        RECT 38.600 67.830 39.560 68.325 ;
        RECT 37.930 67.365 38.310 67.685 ;
        RECT 34.020 65.155 34.985 66.180 ;
        RECT 37.960 65.510 38.280 67.365 ;
        RECT 38.600 66.810 39.565 67.830 ;
        RECT 37.930 65.190 38.310 65.510 ;
        RECT 34.020 64.725 34.980 65.155 ;
        RECT 37.960 65.045 38.280 65.190 ;
        RECT 37.930 64.725 38.310 65.045 ;
        RECT 34.020 60.725 34.980 64.325 ;
        RECT 37.960 64.265 38.280 64.325 ;
        RECT 37.925 63.945 38.305 64.265 ;
        RECT 37.960 63.735 38.280 63.945 ;
        RECT 37.930 63.415 38.310 63.735 ;
        RECT 37.960 61.640 38.280 63.415 ;
        RECT 37.930 61.320 38.310 61.640 ;
        RECT 37.960 61.150 38.280 61.320 ;
        RECT 37.940 60.830 38.320 61.150 ;
        RECT 37.960 60.725 38.280 60.830 ;
        RECT 34.020 58.210 34.980 60.325 ;
        RECT 37.930 60.005 38.310 60.325 ;
        RECT 37.960 59.795 38.280 60.005 ;
        RECT 37.930 59.475 38.310 59.795 ;
        RECT 33.990 57.250 35.010 58.210 ;
        RECT 37.960 57.730 38.280 59.475 ;
        RECT 37.930 57.410 38.310 57.730 ;
        RECT 28.030 56.115 28.470 56.145 ;
        RECT 28.770 56.115 29.210 56.145 ;
        RECT 21.905 55.675 29.210 56.115 ;
        RECT 28.030 55.645 28.470 55.675 ;
        RECT 28.770 55.645 29.210 55.675 ;
        RECT 24.960 51.945 28.480 53.245 ;
        RECT 31.420 52.945 31.800 53.265 ;
        RECT 31.460 52.685 31.780 52.945 ;
        RECT 31.445 52.305 31.780 52.685 ;
        RECT 24.960 50.945 25.280 51.945 ;
        RECT 25.600 51.605 28.480 51.945 ;
        RECT 25.600 51.285 26.560 51.605 ;
        RECT 27.520 51.285 28.480 51.605 ;
        RECT 25.600 50.945 28.480 51.285 ;
        RECT 24.960 49.645 28.480 50.945 ;
        RECT 31.460 49.645 31.780 52.305 ;
        RECT 32.100 51.095 33.060 53.245 ;
        RECT 32.070 50.135 33.090 51.095 ;
        RECT 32.100 49.645 33.060 50.135 ;
        RECT 34.020 49.645 34.980 57.250 ;
        RECT 37.960 56.725 38.280 57.410 ;
        RECT 38.600 56.725 39.560 66.810 ;
        RECT 40.520 66.240 41.480 68.325 ;
        RECT 40.510 65.220 41.480 66.240 ;
        RECT 44.460 65.615 44.780 68.325 ;
        RECT 44.415 65.295 44.795 65.615 ;
        RECT 40.520 64.725 41.480 65.220 ;
        RECT 44.460 65.105 44.780 65.295 ;
        RECT 44.445 64.725 44.780 65.105 ;
        RECT 40.520 60.725 41.480 64.325 ;
        RECT 44.460 61.770 44.780 64.325 ;
        RECT 44.415 61.450 44.795 61.770 ;
        RECT 44.460 61.235 44.780 61.450 ;
        RECT 44.430 60.915 44.810 61.235 ;
        RECT 44.460 60.725 44.780 60.915 ;
        RECT 40.520 58.175 41.480 60.325 ;
        RECT 44.460 60.270 44.780 60.325 ;
        RECT 44.445 59.890 44.780 60.270 ;
        RECT 44.460 59.670 44.780 59.890 ;
        RECT 44.415 59.350 44.795 59.670 ;
        RECT 40.490 57.215 41.510 58.175 ;
        RECT 36.410 56.115 36.850 56.145 ;
        RECT 40.520 56.115 41.480 57.215 ;
        RECT 44.460 56.725 44.780 59.350 ;
        RECT 45.100 56.725 46.060 69.225 ;
        RECT 47.020 67.800 47.980 68.325 ;
        RECT 46.990 66.840 48.010 67.800 ;
        RECT 47.020 60.725 47.980 66.840 ;
        RECT 48.910 63.350 49.990 64.310 ;
        RECT 35.530 55.675 41.480 56.115 ;
        RECT 36.410 55.645 36.850 55.675 ;
        RECT 37.970 53.245 38.290 53.285 ;
        RECT 37.960 52.905 38.290 53.245 ;
        RECT 37.960 52.685 38.280 52.905 ;
        RECT 37.960 52.305 38.285 52.685 ;
        RECT 37.960 49.645 38.280 52.305 ;
        RECT 38.600 51.125 39.560 53.245 ;
        RECT 38.600 50.105 39.610 51.125 ;
        RECT 38.600 49.645 39.560 50.105 ;
        RECT 40.520 49.645 41.480 55.675 ;
        RECT 44.440 52.930 44.820 53.250 ;
        RECT 44.460 52.550 44.780 52.930 ;
        RECT 44.455 52.230 44.835 52.550 ;
        RECT 44.460 49.645 44.780 52.230 ;
        RECT 45.100 51.125 46.060 53.245 ;
        RECT 45.080 50.105 46.060 51.125 ;
        RECT 45.100 49.645 46.060 50.105 ;
        RECT 47.020 49.645 47.980 60.325 ;
        RECT 48.970 60.210 49.930 63.350 ;
        RECT 48.940 59.250 49.960 60.210 ;
        RECT 48.970 58.800 49.930 59.250 ;
        RECT 48.940 57.840 49.960 58.800 ;
        RECT 48.970 57.810 49.930 57.840 ;
        RECT 50.185 57.270 50.840 69.640 ;
        RECT 70.905 68.785 71.470 73.635 ;
        RECT 76.830 69.800 77.790 71.070 ;
        RECT 76.800 68.840 77.820 69.800 ;
        RECT 53.930 68.220 71.525 68.785 ;
        RECT 50.185 56.670 50.870 57.270 ;
        RECT 50.185 56.645 50.840 56.670 ;
        RECT 49.135 56.275 49.545 56.305 ;
        RECT 50.135 56.275 50.545 56.305 ;
        RECT 49.135 55.865 50.945 56.275 ;
        RECT 49.135 55.835 49.545 55.865 ;
        RECT 50.135 55.835 50.945 55.865 ;
        RECT 29.710 48.505 30.730 48.530 ;
        RECT 25.960 48.155 26.280 48.245 ;
        RECT 25.940 48.125 26.280 48.155 ;
        RECT 25.910 47.805 26.290 48.125 ;
        RECT 25.940 47.775 26.280 47.805 ;
        RECT 25.960 47.580 26.280 47.775 ;
        RECT 25.915 47.260 26.295 47.580 ;
        RECT 25.960 44.645 26.280 47.260 ;
        RECT 26.600 44.645 27.560 48.245 ;
        RECT 29.710 47.535 30.760 48.505 ;
        RECT 33.960 48.125 34.280 48.245 ;
        RECT 33.930 47.805 34.310 48.125 ;
        RECT 29.770 46.605 30.760 47.535 ;
        RECT 29.800 44.645 30.760 46.605 ;
        RECT 33.960 47.665 34.280 47.805 ;
        RECT 33.960 47.285 34.285 47.665 ;
        RECT 33.960 44.645 34.280 47.285 ;
        RECT 34.600 44.645 35.560 48.245 ;
        RECT 37.800 44.645 38.760 48.520 ;
        RECT 45.775 48.505 46.735 48.580 ;
        RECT 41.960 48.185 42.280 48.245 ;
        RECT 41.930 47.865 42.310 48.185 ;
        RECT 41.960 47.720 42.280 47.865 ;
        RECT 41.960 47.340 42.285 47.720 ;
        RECT 41.960 44.645 42.280 47.340 ;
        RECT 26.615 43.365 27.545 44.645 ;
        RECT 34.615 43.345 35.545 44.645 ;
        RECT 42.600 43.330 43.560 48.245 ;
        RECT 45.775 47.560 46.760 48.505 ;
        RECT 45.800 44.645 46.760 47.560 ;
        RECT 50.535 43.780 50.945 55.835 ;
        RECT 51.570 51.455 51.890 65.230 ;
        RECT 53.930 51.455 54.495 68.220 ;
        RECT 76.830 67.760 77.790 68.840 ;
        RECT 57.180 66.630 58.200 67.590 ;
        RECT 56.570 65.570 56.890 66.350 ;
        RECT 56.540 65.250 56.920 65.570 ;
        RECT 56.570 62.750 56.890 65.250 ;
        RECT 57.210 62.750 58.170 66.630 ;
        RECT 63.770 66.350 64.610 67.560 ;
        RECT 71.770 66.350 72.610 67.560 ;
        RECT 76.800 66.800 77.820 67.760 ;
        RECT 76.830 66.580 77.790 66.800 ;
        RECT 74.970 66.350 75.930 66.420 ;
        RECT 59.130 64.190 60.090 66.350 ;
        RECT 63.070 66.270 63.390 66.350 ;
        RECT 63.040 65.950 63.420 66.270 ;
        RECT 59.100 63.230 60.120 64.190 ;
        RECT 59.130 62.750 60.090 63.230 ;
        RECT 63.070 62.750 63.390 65.950 ;
        RECT 63.710 62.750 64.670 66.350 ;
        RECT 66.910 61.790 67.870 66.350 ;
        RECT 71.070 66.300 71.390 66.350 ;
        RECT 71.070 66.270 71.410 66.300 ;
        RECT 71.060 65.950 71.440 66.270 ;
        RECT 71.070 65.920 71.410 65.950 ;
        RECT 71.070 65.600 71.390 65.920 ;
        RECT 71.070 65.220 71.410 65.600 ;
        RECT 71.070 62.750 71.390 65.220 ;
        RECT 71.710 62.750 72.670 66.350 ;
        RECT 74.910 65.400 75.930 66.350 ;
        RECT 76.770 65.620 77.850 66.580 ;
        RECT 74.910 62.750 75.870 65.400 ;
        RECT 58.250 61.430 67.870 61.790 ;
        RECT 58.250 59.890 58.610 61.430 ;
        RECT 58.220 59.530 58.640 59.890 ;
        RECT 58.250 59.300 58.610 59.530 ;
        RECT 58.190 58.940 58.670 59.300 ;
        RECT 75.450 59.290 75.810 59.920 ;
        RECT 75.420 58.930 75.840 59.290 ;
        RECT 51.560 50.890 54.495 51.455 ;
        RECT 51.560 47.310 52.125 50.890 ;
        RECT 51.540 46.990 52.125 47.310 ;
        RECT 51.560 46.890 52.125 46.990 ;
        RECT 50.535 43.370 53.045 43.780 ;
        RECT 16.425 38.945 45.525 40.235 ;
        RECT 46.655 40.145 50.940 41.050 ;
        RECT 46.655 38.945 47.560 40.145 ;
        RECT 52.635 40.035 53.045 43.370 ;
        RECT 16.425 38.040 47.560 38.945 ;
        RECT 16.425 36.745 45.525 38.040 ;
        RECT 16.425 33.685 19.915 36.745 ;
        RECT 22.375 33.685 25.865 36.745 ;
        RECT 35.545 33.685 39.035 36.745 ;
        RECT 42.035 33.685 45.525 36.745 ;
        RECT 16.425 30.195 45.525 33.685 ;
        RECT 16.425 21.005 19.915 30.195 ;
        RECT 22.375 27.245 25.865 30.195 ;
        RECT 22.375 24.195 25.975 27.245 ;
        RECT 22.375 21.005 25.865 24.195 ;
        RECT 28.560 23.440 32.630 27.270 ;
        RECT 35.545 21.005 39.035 30.195 ;
        RECT 42.035 21.005 45.525 30.195 ;
        RECT 16.425 17.515 45.525 21.005 ;
        RECT 16.425 14.600 19.915 17.515 ;
        RECT 22.375 14.600 25.865 17.515 ;
        RECT 35.545 14.600 39.035 17.515 ;
        RECT 42.035 14.600 45.525 17.515 ;
        RECT 15.970 11.110 45.525 14.600 ;
        RECT 53.930 14.785 54.495 50.890 ;
        RECT 75.450 42.090 75.810 58.930 ;
        RECT 57.850 41.390 58.210 42.020 ;
        RECT 75.420 41.730 75.840 42.090 ;
        RECT 75.450 41.500 75.810 41.730 ;
        RECT 57.820 41.030 58.240 41.390 ;
        RECT 75.390 41.140 75.870 41.500 ;
        RECT 57.850 24.500 58.210 41.030 ;
        RECT 139.220 37.000 139.520 37.560 ;
        RECT 134.630 36.700 139.550 37.000 ;
        RECT 96.975 33.750 97.890 35.095 ;
        RECT 105.010 33.750 105.850 35.060 ;
        RECT 113.010 33.750 113.850 35.060 ;
        RECT 128.720 34.980 129.600 35.040 ;
        RECT 131.750 34.980 132.630 35.010 ;
        RECT 133.405 34.980 134.220 35.010 ;
        RECT 128.720 34.100 134.270 34.980 ;
        RECT 128.720 34.040 129.600 34.100 ;
        RECT 131.750 34.070 132.630 34.100 ;
        RECT 133.405 34.070 134.220 34.100 ;
        RECT 83.310 33.600 83.630 33.750 ;
        RECT 83.310 33.570 83.650 33.600 ;
        RECT 83.300 33.250 83.680 33.570 ;
        RECT 83.310 33.220 83.650 33.250 ;
        RECT 83.310 32.970 83.630 33.220 ;
        RECT 83.300 32.650 83.680 32.970 ;
        RECT 80.610 31.670 81.690 32.630 ;
        RECT 80.670 31.410 81.630 31.670 ;
        RECT 80.640 30.450 81.660 31.410 ;
        RECT 83.310 31.200 83.630 32.650 ;
        RECT 83.310 31.170 83.650 31.200 ;
        RECT 83.300 30.850 83.680 31.170 ;
        RECT 83.310 30.820 83.650 30.850 ;
        RECT 83.310 30.470 83.630 30.820 ;
        RECT 80.670 29.950 81.630 30.450 ;
        RECT 83.300 30.150 83.680 30.470 ;
        RECT 80.640 28.990 81.660 29.950 ;
        RECT 83.950 29.890 84.910 33.750 ;
        RECT 85.870 30.150 86.830 33.750 ;
        RECT 89.810 32.970 90.130 33.750 ;
        RECT 89.780 32.650 90.160 32.970 ;
        RECT 89.810 31.170 90.130 32.650 ;
        RECT 89.780 30.850 90.160 31.170 ;
        RECT 89.810 30.470 90.130 30.850 ;
        RECT 89.800 30.150 90.180 30.470 ;
        RECT 90.450 29.890 91.410 33.750 ;
        RECT 92.370 33.320 93.330 33.750 ;
        RECT 92.370 32.300 93.370 33.320 ;
        RECT 92.370 31.200 93.330 32.300 ;
        RECT 92.370 30.820 93.350 31.200 ;
        RECT 92.370 30.150 93.330 30.820 ;
        RECT 96.310 30.570 96.630 33.750 ;
        RECT 96.280 30.250 96.660 30.570 ;
        RECT 96.310 30.150 96.630 30.250 ;
        RECT 96.950 30.150 97.910 33.750 ;
        RECT 100.150 29.890 101.110 33.750 ;
        RECT 104.310 31.200 104.630 33.750 ;
        RECT 104.310 30.570 104.650 31.200 ;
        RECT 104.300 30.250 104.680 30.570 ;
        RECT 104.310 30.220 104.650 30.250 ;
        RECT 104.310 30.150 104.630 30.220 ;
        RECT 104.950 30.150 105.910 33.750 ;
        RECT 108.150 29.890 109.110 33.750 ;
        RECT 112.310 31.270 112.630 33.750 ;
        RECT 112.300 30.950 112.680 31.270 ;
        RECT 112.310 30.600 112.630 30.950 ;
        RECT 112.310 30.570 112.650 30.600 ;
        RECT 112.300 30.250 112.680 30.570 ;
        RECT 112.310 30.220 112.650 30.250 ;
        RECT 112.310 30.150 112.630 30.220 ;
        RECT 112.950 30.150 113.910 33.750 ;
        RECT 116.150 29.890 117.110 33.750 ;
        RECT 131.220 31.670 131.580 31.970 ;
        RECT 131.250 30.650 131.550 31.670 ;
        RECT 134.110 31.080 134.410 31.110 ;
        RECT 134.630 31.080 134.930 36.700 ;
        RECT 139.220 36.670 139.520 36.700 ;
        RECT 134.110 30.780 134.930 31.080 ;
        RECT 134.110 30.750 134.410 30.780 ;
        RECT 134.630 30.700 134.930 30.780 ;
        RECT 135.240 31.070 136.120 31.110 ;
        RECT 135.240 30.770 136.740 31.070 ;
        RECT 131.250 30.350 132.190 30.650 ;
        RECT 131.250 30.320 131.550 30.350 ;
        RECT 132.540 29.970 133.420 30.310 ;
        RECT 135.240 29.970 136.120 30.310 ;
        RECT 80.670 28.180 81.630 28.990 ;
        RECT 83.950 28.930 117.470 29.890 ;
        RECT 132.540 29.470 133.420 29.510 ;
        RECT 132.540 29.170 134.040 29.470 ;
        RECT 78.960 26.550 79.920 27.920 ;
        RECT 80.640 27.220 81.660 28.180 ;
        RECT 69.710 25.590 79.920 26.550 ;
        RECT 83.310 26.170 83.630 28.750 ;
        RECT 83.280 25.850 83.660 26.170 ;
        RECT 67.120 24.900 67.500 25.220 ;
        RECT 67.150 24.620 67.470 24.900 ;
        RECT 57.790 24.140 58.270 24.500 ;
        RECT 67.120 24.300 67.500 24.620 ;
        RECT 57.850 23.500 58.210 24.140 ;
        RECT 62.790 24.070 63.110 24.100 ;
        RECT 62.160 23.750 63.810 24.070 ;
        RECT 62.790 23.720 63.110 23.750 ;
        RECT 63.490 20.370 63.810 23.750 ;
        RECT 67.150 21.620 67.470 24.300 ;
        RECT 67.790 21.350 68.750 25.220 ;
        RECT 69.710 21.620 70.670 25.590 ;
        RECT 73.660 22.760 73.980 25.260 ;
        RECT 73.630 22.440 74.010 22.760 ;
        RECT 73.660 21.640 73.980 22.440 ;
        RECT 74.300 21.350 75.260 25.260 ;
        RECT 76.220 21.660 77.180 25.590 ;
        RECT 83.310 25.150 83.630 25.850 ;
        RECT 83.950 25.150 84.910 28.930 ;
        RECT 85.870 25.990 86.830 28.750 ;
        RECT 89.810 28.710 90.130 28.750 ;
        RECT 89.780 28.680 90.130 28.710 ;
        RECT 89.750 28.360 90.130 28.680 ;
        RECT 89.780 28.330 90.130 28.360 ;
        RECT 89.810 27.990 90.130 28.330 ;
        RECT 89.780 27.610 90.130 27.990 ;
        RECT 89.810 26.270 90.130 27.610 ;
        RECT 85.870 25.150 86.870 25.990 ;
        RECT 89.800 25.950 90.180 26.270 ;
        RECT 89.810 25.600 90.130 25.950 ;
        RECT 89.810 25.570 90.150 25.600 ;
        RECT 89.800 25.250 90.180 25.570 ;
        RECT 89.810 25.220 90.150 25.250 ;
        RECT 89.810 25.150 90.130 25.220 ;
        RECT 90.450 25.150 91.410 28.930 ;
        RECT 85.910 24.790 86.870 25.150 ;
        RECT 92.370 24.790 93.330 28.750 ;
        RECT 96.310 28.470 96.630 28.750 ;
        RECT 96.280 28.150 96.660 28.470 ;
        RECT 96.310 26.280 96.630 28.150 ;
        RECT 96.280 25.960 96.660 26.280 ;
        RECT 96.310 25.150 96.630 25.960 ;
        RECT 96.950 25.150 97.910 28.930 ;
        RECT 98.870 28.290 99.830 28.750 ;
        RECT 98.780 27.330 99.830 28.290 ;
        RECT 98.870 26.090 99.830 27.330 ;
        RECT 102.810 26.270 103.130 28.750 ;
        RECT 98.870 25.150 99.870 26.090 ;
        RECT 102.780 25.950 103.160 26.270 ;
        RECT 102.810 25.150 103.130 25.950 ;
        RECT 103.450 25.150 104.410 28.930 ;
        RECT 105.370 26.590 106.330 28.750 ;
        RECT 105.340 25.630 106.360 26.590 ;
        RECT 109.310 26.000 109.630 28.750 ;
        RECT 109.270 25.680 109.650 26.000 ;
        RECT 98.910 24.790 99.870 25.150 ;
        RECT 85.910 23.830 99.870 24.790 ;
        RECT 105.370 24.790 106.330 25.630 ;
        RECT 109.310 25.440 109.630 25.680 ;
        RECT 109.270 25.120 109.650 25.440 ;
        RECT 109.950 25.150 110.910 28.930 ;
        RECT 111.870 28.070 112.830 28.750 ;
        RECT 111.840 27.110 112.860 28.070 ;
        RECT 111.870 26.190 112.830 27.110 ;
        RECT 111.870 25.150 112.870 26.190 ;
        RECT 111.910 24.790 112.870 25.150 ;
        RECT 115.810 25.130 116.130 28.750 ;
        RECT 116.450 26.490 117.410 28.930 ;
        RECT 130.740 28.770 131.620 29.110 ;
        RECT 116.380 25.530 117.410 26.490 ;
        RECT 116.450 25.150 117.410 25.530 ;
        RECT 118.370 28.100 119.330 28.750 ;
        RECT 118.370 27.080 119.370 28.100 ;
        RECT 130.110 27.470 130.410 27.530 ;
        RECT 130.740 27.470 131.620 27.510 ;
        RECT 130.110 27.170 131.620 27.470 ;
        RECT 118.370 25.150 119.330 27.080 ;
        RECT 130.110 26.900 130.440 27.170 ;
        RECT 130.080 26.600 130.440 26.900 ;
        RECT 132.540 26.770 133.420 27.110 ;
        RECT 105.370 23.830 112.900 24.790 ;
        RECT 83.310 22.670 83.630 22.750 ;
        RECT 83.280 22.350 83.660 22.670 ;
        RECT 67.710 21.320 68.920 21.350 ;
        RECT 74.200 21.320 75.450 21.350 ;
        RECT 67.680 20.830 68.950 21.320 ;
        RECT 67.680 20.800 68.200 20.830 ;
        RECT 68.430 20.800 68.950 20.830 ;
        RECT 74.170 20.800 75.480 21.320 ;
        RECT 67.710 20.770 68.170 20.800 ;
        RECT 68.460 20.770 68.920 20.800 ;
        RECT 74.200 20.780 75.450 20.800 ;
        RECT 74.200 20.770 74.660 20.780 ;
        RECT 74.990 20.770 75.450 20.780 ;
        RECT 67.120 20.370 67.440 20.450 ;
        RECT 63.490 20.050 67.440 20.370 ;
        RECT 67.120 17.870 67.440 20.050 ;
        RECT 67.090 17.550 67.470 17.870 ;
        RECT 67.120 16.820 67.440 17.550 ;
        RECT 67.760 16.590 68.720 20.450 ;
        RECT 69.680 16.850 70.640 20.450 ;
        RECT 73.660 17.900 73.980 20.450 ;
        RECT 73.660 17.870 74.010 17.900 ;
        RECT 73.660 17.550 74.040 17.870 ;
        RECT 73.660 17.520 74.010 17.550 ;
        RECT 73.660 17.200 73.980 17.520 ;
        RECT 73.660 16.850 74.010 17.200 ;
        RECT 73.690 16.820 74.010 16.850 ;
        RECT 74.300 16.590 75.260 20.450 ;
        RECT 76.220 20.020 77.180 20.450 ;
        RECT 76.070 19.000 77.180 20.020 ;
        RECT 83.310 19.470 83.630 22.350 ;
        RECT 83.950 21.190 84.910 22.750 ;
        RECT 83.920 20.230 84.940 21.190 ;
        RECT 83.280 19.150 83.660 19.470 ;
        RECT 83.950 19.150 84.910 20.230 ;
        RECT 85.870 19.150 86.830 22.750 ;
        RECT 89.810 20.200 90.130 22.750 ;
        RECT 90.450 22.120 91.410 22.750 ;
        RECT 90.410 21.100 91.410 22.120 ;
        RECT 90.450 20.890 91.410 21.100 ;
        RECT 92.370 22.190 93.330 22.750 ;
        RECT 92.370 21.230 93.400 22.190 ;
        RECT 89.810 20.170 90.150 20.200 ;
        RECT 89.800 19.850 90.180 20.170 ;
        RECT 90.420 19.930 91.440 20.890 ;
        RECT 89.810 19.820 90.150 19.850 ;
        RECT 89.810 19.500 90.130 19.820 ;
        RECT 89.810 19.470 90.150 19.500 ;
        RECT 89.800 19.150 90.180 19.470 ;
        RECT 90.450 19.150 91.410 19.930 ;
        RECT 92.370 19.150 93.330 21.230 ;
        RECT 96.310 20.170 96.630 22.750 ;
        RECT 96.950 21.920 97.910 22.750 ;
        RECT 98.870 22.290 99.830 22.750 ;
        RECT 102.810 22.670 103.130 22.750 ;
        RECT 102.780 22.350 103.160 22.670 ;
        RECT 96.950 20.900 97.970 21.920 ;
        RECT 98.870 21.330 99.900 22.290 ;
        RECT 96.950 20.590 97.910 20.900 ;
        RECT 96.300 19.850 96.680 20.170 ;
        RECT 96.310 19.500 96.630 19.850 ;
        RECT 96.880 19.630 97.910 20.590 ;
        RECT 96.310 19.150 96.650 19.500 ;
        RECT 96.950 19.150 97.910 19.630 ;
        RECT 98.870 19.150 99.830 21.330 ;
        RECT 102.810 20.170 103.130 22.350 ;
        RECT 103.450 21.420 104.410 22.750 ;
        RECT 105.370 22.190 106.330 22.750 ;
        RECT 103.450 20.400 104.470 21.420 ;
        RECT 105.370 21.230 106.400 22.190 ;
        RECT 102.780 19.850 103.160 20.170 ;
        RECT 102.810 19.670 103.130 19.850 ;
        RECT 102.780 19.350 103.160 19.670 ;
        RECT 102.810 19.150 103.130 19.350 ;
        RECT 83.310 19.120 83.630 19.150 ;
        RECT 89.830 19.120 90.150 19.150 ;
        RECT 96.330 19.120 96.650 19.150 ;
        RECT 76.220 16.850 77.180 19.000 ;
        RECT 81.025 17.745 81.635 18.295 ;
        RECT 83.310 18.070 83.630 18.750 ;
        RECT 83.280 17.750 83.660 18.070 ;
        RECT 81.055 17.305 81.605 17.745 ;
        RECT 81.055 16.755 81.665 17.305 ;
        RECT 67.760 15.630 71.930 16.590 ;
        RECT 74.300 15.630 78.930 16.590 ;
        RECT 70.970 15.290 71.930 15.630 ;
        RECT 77.970 15.290 78.930 15.630 ;
        RECT 67.100 15.260 67.420 15.290 ;
        RECT 66.950 14.785 67.490 15.260 ;
        RECT 53.930 14.220 67.490 14.785 ;
        RECT 67.100 11.690 67.420 14.220 ;
        RECT 67.740 11.690 68.700 15.290 ;
        RECT 70.940 14.830 71.930 15.290 ;
        RECT 74.140 15.200 74.460 15.290 ;
        RECT 74.140 15.170 74.510 15.200 ;
        RECT 74.140 14.850 74.540 15.170 ;
        RECT 70.940 11.690 71.900 14.830 ;
        RECT 74.140 14.820 74.510 14.850 ;
        RECT 74.140 14.500 74.460 14.820 ;
        RECT 74.140 14.120 74.510 14.500 ;
        RECT 74.140 11.690 74.460 14.120 ;
        RECT 74.780 11.690 75.740 15.290 ;
        RECT 77.970 14.930 78.940 15.290 ;
        RECT 77.980 11.690 78.940 14.930 ;
        RECT 35.545 11.015 39.035 11.110 ;
        RECT 67.800 10.560 68.640 11.690 ;
        RECT 74.840 11.430 75.680 11.690 ;
        RECT 74.810 10.590 75.710 11.430 ;
        RECT 81.055 10.915 81.605 16.755 ;
        RECT 83.310 16.200 83.630 17.750 ;
        RECT 83.310 16.170 83.650 16.200 ;
        RECT 83.300 15.850 83.680 16.170 ;
        RECT 83.310 15.820 83.650 15.850 ;
        RECT 83.310 15.570 83.630 15.820 ;
        RECT 83.300 15.250 83.680 15.570 ;
        RECT 83.310 15.150 83.630 15.250 ;
        RECT 83.950 14.410 84.910 18.750 ;
        RECT 85.870 18.200 86.830 18.750 ;
        RECT 85.865 17.215 86.910 18.200 ;
        RECT 85.870 15.150 86.830 17.215 ;
        RECT 89.810 16.070 90.130 18.750 ;
        RECT 89.800 15.750 90.180 16.070 ;
        RECT 89.810 15.500 90.130 15.750 ;
        RECT 89.810 15.470 90.150 15.500 ;
        RECT 89.800 15.150 90.180 15.470 ;
        RECT 89.830 15.120 90.150 15.150 ;
        RECT 90.450 14.410 91.410 18.750 ;
        RECT 92.370 18.320 93.330 18.750 ;
        RECT 92.370 17.300 93.370 18.320 ;
        RECT 92.370 15.150 93.330 17.300 ;
        RECT 96.310 15.470 96.630 18.750 ;
        RECT 96.280 15.150 96.660 15.470 ;
        RECT 96.310 15.120 96.630 15.150 ;
        RECT 96.950 14.410 97.910 18.750 ;
        RECT 98.870 15.150 99.830 18.750 ;
        RECT 102.810 18.070 103.130 18.780 ;
        RECT 102.780 17.750 103.160 18.070 ;
        RECT 102.810 15.150 103.130 17.750 ;
        RECT 103.450 15.150 104.410 20.400 ;
        RECT 105.370 15.150 106.330 21.230 ;
        RECT 109.310 20.070 109.630 22.750 ;
        RECT 109.300 19.750 109.680 20.070 ;
        RECT 109.310 19.600 109.630 19.750 ;
        RECT 109.310 19.570 109.650 19.600 ;
        RECT 109.300 19.250 109.680 19.570 ;
        RECT 109.310 19.220 109.650 19.250 ;
        RECT 109.310 19.150 109.630 19.220 ;
        RECT 109.950 19.150 110.910 22.750 ;
        RECT 111.870 22.190 112.830 22.750 ;
        RECT 111.780 21.230 112.830 22.190 ;
        RECT 111.870 19.150 112.830 21.230 ;
        RECT 118.310 21.070 118.630 24.250 ;
        RECT 118.300 20.750 118.680 21.070 ;
        RECT 118.310 20.650 118.630 20.750 ;
        RECT 118.310 19.570 118.630 20.250 ;
        RECT 118.300 19.250 118.680 19.570 ;
        RECT 109.310 17.970 109.630 18.750 ;
        RECT 109.280 17.650 109.660 17.970 ;
        RECT 109.310 15.150 109.630 17.650 ;
        RECT 109.950 16.530 110.910 18.750 ;
        RECT 111.870 18.120 112.830 18.750 ;
        RECT 111.870 17.100 112.870 18.120 ;
        RECT 109.940 15.570 110.960 16.530 ;
        RECT 109.950 15.150 110.910 15.570 ;
        RECT 111.870 15.150 112.830 17.100 ;
        RECT 118.310 16.650 118.630 19.250 ;
        RECT 118.310 16.070 118.630 16.250 ;
        RECT 118.280 15.750 118.660 16.070 ;
        RECT 118.310 15.570 118.630 15.750 ;
        RECT 118.300 15.250 118.680 15.570 ;
        RECT 103.150 14.410 104.110 14.450 ;
        RECT 83.890 14.010 104.110 14.410 ;
        RECT 83.330 13.770 83.650 13.800 ;
        RECT 83.300 13.450 83.680 13.770 ;
        RECT 83.310 13.420 83.650 13.450 ;
        RECT 83.310 13.070 83.630 13.420 ;
        RECT 83.300 12.750 83.680 13.070 ;
        RECT 81.005 10.365 81.615 10.915 ;
        RECT 81.055 10.045 81.605 10.365 ;
        RECT 83.310 10.150 83.630 12.750 ;
        RECT 83.950 10.150 84.910 13.750 ;
        RECT 87.150 10.150 88.110 14.010 ;
        RECT 91.310 13.700 91.630 13.750 ;
        RECT 91.310 13.670 91.650 13.700 ;
        RECT 91.300 13.350 91.680 13.670 ;
        RECT 91.310 13.320 91.650 13.350 ;
        RECT 91.310 13.100 91.630 13.320 ;
        RECT 91.310 13.070 91.650 13.100 ;
        RECT 91.300 12.750 91.680 13.070 ;
        RECT 91.310 12.720 91.650 12.750 ;
        RECT 91.310 10.150 91.630 12.720 ;
        RECT 91.950 10.150 92.910 13.750 ;
        RECT 95.150 10.150 96.110 14.010 ;
        RECT 103.150 13.820 104.110 14.010 ;
        RECT 99.310 13.670 99.630 13.750 ;
        RECT 99.280 13.350 99.660 13.670 ;
        RECT 99.310 10.150 99.630 13.350 ;
        RECT 81.025 9.495 81.635 10.045 ;
        RECT 84.010 5.770 84.850 10.150 ;
        RECT 91.970 7.170 92.890 10.150 ;
        RECT 91.960 6.200 92.905 7.170 ;
        RECT 83.980 4.930 84.880 5.770 ;
        RECT 91.940 5.280 92.920 6.200 ;
        RECT 91.960 5.270 92.905 5.280 ;
        RECT 99.950 5.150 100.910 13.750 ;
        RECT 103.150 12.800 104.170 13.820 ;
        RECT 118.310 13.770 118.630 15.250 ;
        RECT 107.310 12.970 107.630 13.750 ;
        RECT 103.150 10.150 104.110 12.800 ;
        RECT 107.300 12.650 107.680 12.970 ;
        RECT 107.310 10.150 107.630 12.650 ;
        RECT 107.950 10.150 108.910 13.750 ;
        RECT 109.870 12.390 110.830 13.750 ;
        RECT 118.300 13.450 118.680 13.770 ;
        RECT 118.310 13.070 118.630 13.450 ;
        RECT 118.300 12.750 118.680 13.070 ;
        RECT 118.310 12.650 118.630 12.750 ;
        RECT 118.950 12.650 119.910 24.250 ;
        RECT 120.870 20.650 121.830 24.250 ;
        RECT 120.870 19.790 121.830 20.250 ;
        RECT 120.840 18.830 121.860 19.790 ;
        RECT 120.870 16.650 121.830 18.830 ;
        RECT 120.870 14.190 121.830 16.250 ;
        RECT 130.140 15.470 130.440 26.600 ;
        RECT 132.540 26.270 133.420 26.310 ;
        RECT 133.740 26.270 134.040 29.170 ;
        RECT 136.440 28.270 136.740 30.770 ;
        RECT 137.040 28.270 137.920 28.310 ;
        RECT 136.440 27.970 137.920 28.270 ;
        RECT 135.240 27.570 136.120 27.910 ;
        RECT 132.540 25.970 134.040 26.270 ;
        RECT 137.040 25.870 137.920 25.910 ;
        RECT 137.040 25.570 138.540 25.870 ;
        RECT 137.040 25.070 137.920 25.110 ;
        RECT 136.440 24.770 137.920 25.070 ;
        RECT 132.540 24.370 133.420 24.710 ;
        RECT 135.240 24.370 136.120 24.710 ;
        RECT 135.240 23.870 136.120 23.910 ;
        RECT 136.440 23.870 136.740 24.770 ;
        RECT 135.240 23.570 136.740 23.870 ;
        RECT 130.740 23.470 131.620 23.510 ;
        RECT 130.740 23.170 132.240 23.470 ;
        RECT 131.940 22.270 132.240 23.170 ;
        RECT 132.540 22.770 133.420 23.110 ;
        RECT 135.240 22.770 136.120 23.110 ;
        RECT 132.540 22.270 133.420 22.310 ;
        RECT 131.940 21.970 133.420 22.270 ;
        RECT 136.440 21.070 136.740 23.570 ;
        RECT 137.040 21.870 137.920 21.910 ;
        RECT 138.240 21.870 138.540 25.570 ;
        RECT 137.040 21.570 138.540 21.870 ;
        RECT 137.040 21.070 137.920 21.110 ;
        RECT 136.440 20.770 137.920 21.070 ;
        RECT 132.540 20.370 133.420 20.710 ;
        RECT 135.240 20.370 136.120 20.710 ;
        RECT 137.540 19.540 137.840 20.100 ;
        RECT 130.740 19.470 131.620 19.510 ;
        RECT 130.740 19.170 131.640 19.470 ;
        RECT 137.510 19.240 137.870 19.540 ;
        RECT 131.340 18.870 132.240 19.170 ;
        RECT 131.940 15.870 132.240 18.870 ;
        RECT 137.540 18.700 137.840 19.240 ;
        RECT 137.480 18.400 137.900 18.700 ;
        RECT 132.540 17.970 133.420 18.310 ;
        RECT 135.240 17.970 136.120 18.310 ;
        RECT 132.540 16.370 133.420 16.710 ;
        RECT 135.240 16.370 136.120 16.710 ;
        RECT 132.540 15.870 133.420 15.910 ;
        RECT 131.940 15.570 133.420 15.870 ;
        RECT 135.240 15.570 136.120 15.910 ;
        RECT 130.740 15.470 131.620 15.510 ;
        RECT 130.140 15.170 131.620 15.470 ;
        RECT 130.140 15.120 130.440 15.170 ;
        RECT 135.240 15.070 136.120 15.110 ;
        RECT 138.240 15.070 138.540 21.570 ;
        RECT 135.240 14.770 138.540 15.070 ;
        RECT 130.810 14.670 131.110 14.730 ;
        RECT 124.920 14.635 131.650 14.670 ;
        RECT 124.795 14.370 131.650 14.635 ;
        RECT 120.840 13.230 121.860 14.190 ;
        RECT 120.870 12.390 121.830 13.230 ;
        RECT 109.870 11.430 121.830 12.390 ;
        RECT 109.870 10.150 110.830 11.430 ;
        RECT 124.795 10.855 125.345 14.370 ;
        RECT 130.810 14.310 131.110 14.370 ;
        RECT 132.540 13.970 133.420 14.310 ;
        RECT 135.240 13.970 136.120 14.310 ;
        RECT 132.540 13.170 133.420 13.510 ;
        RECT 135.240 13.170 136.120 13.510 ;
        RECT 132.540 12.370 133.420 12.710 ;
        RECT 135.240 12.370 136.120 12.710 ;
        RECT 124.755 10.305 125.365 10.855 ;
        RECT 124.795 10.045 125.345 10.305 ;
        RECT 124.765 9.495 125.375 10.045 ;
        RECT 126.660 9.750 127.540 9.810 ;
        RECT 129.220 9.750 130.100 9.780 ;
        RECT 130.900 9.750 131.780 9.780 ;
        RECT 126.660 8.870 131.780 9.750 ;
        RECT 126.660 8.810 127.540 8.870 ;
        RECT 129.220 8.840 130.100 8.870 ;
        RECT 130.900 8.840 131.780 8.870 ;
        RECT 84.010 4.850 84.850 4.930 ;
      LAYER met2 ;
        RECT 159.320 108.640 160.660 108.860 ;
        RECT 145.280 108.615 160.660 108.640 ;
        RECT 137.620 108.470 138.610 108.480 ;
        RECT 137.620 108.190 138.645 108.470 ;
        RECT 137.620 108.180 138.610 108.190 ;
        RECT 145.260 107.785 160.660 108.615 ;
        RECT 145.280 107.760 160.660 107.785 ;
        RECT 140.890 107.680 141.170 107.715 ;
        RECT 140.880 107.380 141.900 107.680 ;
        RECT 159.320 107.560 160.660 107.760 ;
        RECT 140.890 107.345 141.170 107.380 ;
        RECT 142.580 106.080 143.460 106.420 ;
        RECT 145.280 106.080 146.160 106.420 ;
        RECT 142.580 105.280 143.460 105.620 ;
        RECT 145.280 105.280 146.160 105.620 ;
        RECT 142.580 104.480 143.460 104.820 ;
        RECT 145.280 104.480 146.160 104.820 ;
        RECT 156.710 103.940 158.050 104.130 ;
        RECT 142.580 103.915 158.050 103.940 ;
        RECT 142.560 103.085 158.050 103.915 ;
        RECT 142.580 103.060 158.050 103.085 ;
        RECT 156.710 102.830 158.050 103.060 ;
        RECT 45.285 96.510 46.280 97.635 ;
        RECT 45.255 95.600 46.305 96.510 ;
        RECT 52.840 95.920 53.920 97.650 ;
        RECT 60.560 97.575 61.400 97.600 ;
        RECT 60.540 96.785 61.420 97.575 ;
        RECT 52.855 95.690 53.905 95.920 ;
        RECT 45.285 95.080 46.280 95.600 ;
        RECT 45.270 94.120 46.290 95.080 ;
        RECT 45.300 93.900 46.260 94.120 ;
        RECT 52.900 94.020 53.860 95.690 ;
        RECT 60.560 95.020 61.400 96.785 ;
        RECT 60.530 94.180 61.430 95.020 ;
        RECT 45.270 92.940 46.290 93.900 ;
        RECT 52.870 93.060 53.890 94.020 ;
        RECT 60.560 94.000 61.400 94.180 ;
        RECT 60.530 93.160 61.430 94.000 ;
        RECT 60.560 93.130 61.400 93.160 ;
        RECT 45.300 92.790 46.260 92.940 ;
        RECT 76.830 92.190 77.790 96.615 ;
        RECT 69.795 92.140 70.625 92.160 ;
        RECT 70.855 92.140 71.685 92.160 ;
        RECT 5.025 90.910 8.850 92.090 ;
        RECT 67.140 91.260 71.710 92.140 ;
        RECT 69.795 91.240 70.625 91.260 ;
        RECT 70.855 91.240 71.685 91.260 ;
        RECT 75.335 91.230 77.790 92.190 ;
        RECT 45.965 90.770 46.315 90.790 ;
        RECT 46.465 90.770 46.815 90.790 ;
        RECT 45.940 90.370 48.170 90.770 ;
        RECT 45.965 90.350 46.315 90.370 ;
        RECT 46.465 90.350 46.815 90.370 ;
        RECT 44.630 88.180 45.010 88.500 ;
        RECT 42.950 87.820 43.270 87.850 ;
        RECT 43.550 87.820 43.870 87.850 ;
        RECT 44.660 87.840 44.980 88.180 ;
        RECT 52.280 87.840 52.600 88.500 ;
        RECT 59.880 87.840 60.200 88.430 ;
        RECT 66.585 87.985 67.185 88.030 ;
        RECT 66.540 87.840 67.230 87.985 ;
        RECT 68.610 87.840 68.970 87.880 ;
        RECT 44.660 87.820 74.120 87.840 ;
        RECT 30.860 85.350 31.820 87.580 ;
        RECT 40.560 86.850 41.520 87.680 ;
        RECT 42.950 87.520 74.120 87.820 ;
        RECT 42.950 87.500 45.270 87.520 ;
        RECT 42.950 87.470 43.270 87.500 ;
        RECT 43.550 87.470 43.870 87.500 ;
        RECT 44.660 87.490 44.980 87.500 ;
        RECT 66.540 87.385 67.230 87.520 ;
        RECT 66.585 87.340 67.185 87.385 ;
        RECT 68.640 87.000 68.940 87.520 ;
        RECT 40.560 85.890 50.920 86.850 ;
        RECT 68.630 86.110 68.950 87.000 ;
        RECT 70.110 86.680 70.990 86.710 ;
        RECT 73.095 86.680 73.925 86.700 ;
        RECT 75.105 86.680 75.935 86.700 ;
        RECT 49.960 85.350 50.920 85.890 ;
        RECT 68.420 85.790 68.980 86.110 ;
        RECT 70.110 85.800 75.960 86.680 ;
        RECT 68.420 85.760 68.950 85.790 ;
        RECT 24.775 83.535 25.105 85.065 ;
        RECT 30.860 84.390 48.980 85.350 ;
        RECT 49.960 84.390 54.500 85.350 ;
        RECT 68.420 85.330 68.740 85.760 ;
        RECT 68.395 85.050 68.765 85.330 ;
        RECT 70.110 85.200 70.990 85.800 ;
        RECT 73.095 85.780 73.925 85.800 ;
        RECT 75.105 85.780 75.935 85.800 ;
        RECT 68.420 84.430 68.740 85.050 ;
        RECT 24.775 83.205 28.870 83.535 ;
        RECT 25.960 72.350 26.280 76.465 ;
        RECT 15.620 61.460 16.120 61.485 ;
        RECT 15.600 61.010 16.140 61.460 ;
        RECT 15.620 59.860 16.120 61.010 ;
        RECT 14.275 59.360 16.120 59.860 ;
        RECT 25.940 48.125 26.260 48.155 ;
        RECT 26.910 48.125 27.230 76.475 ;
        RECT 28.540 68.325 28.870 83.205 ;
        RECT 34.280 77.430 34.600 82.660 ;
        RECT 29.300 77.110 34.600 77.430 ;
        RECT 29.300 68.935 29.620 77.110 ;
        RECT 42.950 74.780 43.270 82.940 ;
        RECT 46.550 82.790 47.570 83.750 ;
        RECT 46.580 82.450 47.540 82.790 ;
        RECT 45.260 81.490 47.540 82.450 ;
        RECT 45.260 81.250 46.220 81.490 ;
        RECT 45.230 80.290 46.250 81.250 ;
        RECT 48.020 81.210 48.980 84.390 ;
        RECT 52.250 82.790 53.270 83.750 ;
        RECT 52.280 82.450 53.240 82.790 ;
        RECT 46.580 80.250 48.980 81.210 ;
        RECT 50.960 81.490 53.240 82.450 ;
        RECT 50.960 81.150 51.920 81.490 ;
        RECT 53.540 81.190 54.500 84.390 ;
        RECT 68.395 84.150 68.765 84.430 ;
        RECT 70.080 84.320 71.020 85.200 ;
        RECT 68.420 84.130 68.740 84.150 ;
        RECT 57.950 82.790 58.970 83.750 ;
        RECT 62.060 83.030 62.380 83.060 ;
        RECT 57.980 82.450 58.940 82.790 ;
        RECT 62.060 82.710 65.830 83.030 ;
        RECT 62.060 82.680 62.400 82.710 ;
        RECT 50.930 80.190 51.950 81.150 ;
        RECT 52.250 80.230 54.500 81.190 ;
        RECT 56.660 81.490 58.940 82.450 ;
        RECT 62.080 82.180 62.400 82.680 ;
        RECT 56.660 80.260 57.620 81.490 ;
        RECT 57.980 79.650 58.940 79.680 ;
        RECT 52.280 79.550 53.240 79.580 ;
        RECT 52.280 78.590 56.780 79.550 ;
        RECT 57.980 78.690 71.805 79.650 ;
        RECT 57.980 78.660 58.940 78.690 ;
        RECT 52.280 78.560 53.240 78.590 ;
        RECT 55.820 77.260 56.780 78.590 ;
        RECT 69.320 77.260 70.230 77.305 ;
        RECT 55.820 76.300 71.835 77.260 ;
        RECT 69.320 76.255 70.230 76.300 ;
        RECT 41.950 74.460 43.270 74.780 ;
        RECT 31.180 73.175 31.500 73.720 ;
        RECT 41.950 73.205 42.270 74.460 ;
        RECT 33.940 73.175 34.260 73.205 ;
        RECT 41.950 73.175 42.280 73.205 ;
        RECT 31.150 72.855 42.285 73.175 ;
        RECT 33.935 72.825 34.260 72.855 ;
        RECT 41.960 72.825 42.285 72.855 ;
        RECT 33.935 72.580 34.255 72.825 ;
        RECT 33.905 72.260 34.285 72.580 ;
        RECT 41.965 72.250 42.285 72.825 ;
        RECT 76.830 71.040 77.790 91.230 ;
        RECT 87.880 85.680 88.280 85.710 ;
        RECT 88.950 85.680 89.350 85.710 ;
        RECT 85.165 85.280 89.380 85.680 ;
        RECT 87.880 85.250 88.280 85.280 ;
        RECT 88.950 85.250 89.350 85.280 ;
        RECT 79.130 85.030 79.530 85.060 ;
        RECT 82.460 85.055 82.860 85.075 ;
        RECT 83.035 85.055 83.385 85.075 ;
        RECT 82.400 85.030 83.410 85.055 ;
        RECT 79.130 84.655 83.410 85.030 ;
        RECT 79.130 84.630 82.860 84.655 ;
        RECT 83.035 84.635 83.385 84.655 ;
        RECT 79.130 84.600 79.530 84.630 ;
        RECT 82.500 81.120 83.380 81.460 ;
        RECT 85.200 81.120 86.080 81.460 ;
        RECT 99.410 80.180 100.610 80.190 ;
        RECT 99.410 79.900 100.645 80.180 ;
        RECT 99.410 79.890 100.610 79.900 ;
        RECT 82.480 75.770 83.360 76.110 ;
        RECT 85.180 75.770 86.060 76.110 ;
        RECT 29.800 70.365 30.760 70.395 ;
        RECT 37.720 70.365 38.760 70.375 ;
        RECT 29.800 69.405 46.750 70.365 ;
        RECT 76.800 70.080 77.820 71.040 ;
        RECT 76.830 69.800 77.790 69.830 ;
        RECT 29.800 69.375 30.760 69.405 ;
        RECT 37.720 69.395 38.760 69.405 ;
        RECT 29.300 68.625 32.720 68.935 ;
        RECT 76.800 68.840 77.820 69.800 ;
        RECT 76.830 68.810 77.790 68.840 ;
        RECT 29.300 68.615 38.280 68.625 ;
        RECT 28.540 68.025 31.785 68.325 ;
        RECT 32.400 68.305 38.280 68.615 ;
        RECT 31.465 66.680 31.785 68.025 ;
        RECT 32.065 67.170 37.105 67.830 ;
        RECT 37.960 67.335 38.280 68.305 ;
        RECT 38.565 67.800 39.575 67.825 ;
        RECT 47.020 67.800 47.980 67.830 ;
        RECT 38.565 67.170 47.980 67.800 ;
        RECT 32.065 66.840 47.980 67.170 ;
        RECT 32.065 66.820 39.575 66.840 ;
        RECT 31.465 66.360 35.610 66.680 ;
        RECT 30.190 65.185 35.015 66.150 ;
        RECT 35.290 66.005 35.610 66.360 ;
        RECT 36.095 66.270 39.575 66.820 ;
        RECT 47.020 66.810 47.980 66.840 ;
        RECT 57.210 67.590 58.170 67.620 ;
        RECT 57.210 66.630 75.930 67.590 ;
        RECT 57.210 66.600 58.170 66.630 ;
        RECT 74.970 66.390 75.930 66.630 ;
        RECT 63.070 66.270 63.390 66.300 ;
        RECT 68.420 66.270 68.740 66.315 ;
        RECT 69.090 66.270 69.370 66.315 ;
        RECT 71.090 66.270 71.410 66.300 ;
        RECT 35.290 65.685 38.890 66.005 ;
        RECT 30.190 63.160 31.155 65.185 ;
        RECT 37.960 65.085 38.280 65.540 ;
        RECT 37.960 65.045 38.290 65.085 ;
        RECT 35.305 64.725 38.290 65.045 ;
        RECT 31.455 63.700 31.775 64.270 ;
        RECT 35.305 63.700 35.625 64.725 ;
        RECT 37.960 64.695 38.280 64.725 ;
        RECT 31.425 63.380 35.625 63.700 ;
        RECT 37.955 63.765 38.275 64.295 ;
        RECT 37.955 63.735 38.280 63.765 ;
        RECT 38.570 63.735 38.890 65.685 ;
        RECT 40.480 65.250 43.300 66.210 ;
        RECT 56.540 65.850 56.920 66.170 ;
        RECT 63.040 65.950 71.440 66.270 ;
        RECT 37.955 63.415 38.890 63.735 ;
        RECT 37.960 63.385 38.280 63.415 ;
        RECT 40.580 63.160 40.900 63.165 ;
        RECT 30.185 62.790 41.435 63.160 ;
        RECT 30.190 58.210 31.155 62.790 ;
        RECT 40.580 62.785 40.900 62.790 ;
        RECT 42.340 62.285 43.300 65.250 ;
        RECT 44.445 65.075 44.765 65.645 ;
        RECT 56.570 65.570 56.890 65.850 ;
        RECT 59.190 65.570 59.510 65.600 ;
        RECT 63.070 65.570 63.390 65.950 ;
        RECT 68.420 65.945 68.740 65.950 ;
        RECT 69.090 65.945 69.370 65.950 ;
        RECT 71.090 65.570 71.410 65.950 ;
        RECT 54.810 65.560 60.040 65.570 ;
        RECT 54.780 65.250 60.040 65.560 ;
        RECT 63.040 65.250 63.420 65.570 ;
        RECT 71.060 65.250 71.440 65.570 ;
        RECT 74.940 65.430 75.960 66.390 ;
        RECT 44.415 64.755 44.795 65.075 ;
        RECT 34.010 61.910 43.305 62.285 ;
        RECT 34.535 61.905 34.855 61.910 ;
        RECT 31.430 61.335 35.610 61.655 ;
        RECT 31.460 60.725 31.780 61.335 ;
        RECT 35.290 60.325 35.610 61.335 ;
        RECT 37.960 61.640 38.280 61.670 ;
        RECT 37.960 61.320 38.920 61.640 ;
        RECT 37.960 61.290 38.290 61.320 ;
        RECT 37.970 60.800 38.290 61.290 ;
        RECT 37.960 60.325 38.280 60.355 ;
        RECT 31.455 59.660 31.775 60.300 ;
        RECT 35.290 60.005 38.280 60.325 ;
        RECT 31.425 59.340 37.415 59.660 ;
        RECT 37.960 59.445 38.280 60.005 ;
        RECT 37.095 59.090 37.415 59.340 ;
        RECT 38.600 59.090 38.920 61.320 ;
        RECT 37.095 58.770 38.920 59.090 ;
        RECT 34.020 58.210 34.980 58.240 ;
        RECT 30.190 57.250 34.980 58.210 ;
        RECT 37.095 58.025 37.415 58.770 ;
        RECT 40.520 58.175 41.480 58.205 ;
        RECT 42.340 58.175 43.300 61.910 ;
        RECT 44.445 61.265 44.765 64.755 ;
        RECT 54.780 62.580 55.130 65.250 ;
        RECT 56.570 65.220 56.890 65.250 ;
        RECT 59.190 65.220 59.510 65.250 ;
        RECT 44.445 61.235 44.780 61.265 ;
        RECT 54.770 61.235 55.130 62.580 ;
        RECT 59.130 62.790 60.090 64.220 ;
        RECT 59.130 61.830 77.030 62.790 ;
        RECT 44.445 60.915 55.130 61.235 ;
        RECT 44.445 60.885 44.780 60.915 ;
        RECT 54.810 60.900 55.130 60.915 ;
        RECT 44.445 60.240 44.765 60.885 ;
        RECT 44.415 59.920 44.795 60.240 ;
        RECT 44.445 59.320 44.765 59.920 ;
        RECT 48.970 58.800 49.930 60.240 ;
        RECT 37.055 57.710 37.460 58.025 ;
        RECT 37.960 57.730 38.280 57.760 ;
        RECT 34.020 57.220 34.980 57.250 ;
        RECT 37.095 57.065 37.415 57.710 ;
        RECT 37.930 57.410 39.000 57.730 ;
        RECT 37.960 57.130 38.280 57.410 ;
        RECT 37.930 56.810 38.310 57.130 ;
        RECT 38.680 56.275 39.000 57.410 ;
        RECT 40.520 57.215 43.300 58.175 ;
        RECT 48.940 57.840 53.280 58.800 ;
        RECT 48.970 57.810 49.930 57.840 ;
        RECT 50.240 57.270 50.840 57.300 ;
        RECT 40.520 57.185 41.480 57.215 ;
        RECT 50.140 56.670 51.840 57.270 ;
        RECT 50.240 56.640 50.840 56.670 ;
        RECT 38.680 56.270 50.575 56.275 ;
        RECT 35.560 56.115 36.000 56.145 ;
        RECT 28.000 55.675 36.880 56.115 ;
        RECT 38.555 55.865 50.575 56.270 ;
        RECT 35.560 55.645 36.000 55.675 ;
        RECT 31.240 55.135 31.520 55.160 ;
        RECT 47.550 55.135 47.870 55.165 ;
        RECT 51.440 55.135 51.840 56.670 ;
        RECT 30.310 54.815 51.860 55.135 ;
        RECT 31.240 54.790 31.520 54.815 ;
        RECT 47.550 54.785 47.870 54.815 ;
        RECT 31.450 52.655 31.770 53.295 ;
        RECT 37.940 52.935 38.320 53.255 ;
        RECT 34.560 52.655 34.880 52.685 ;
        RECT 37.970 52.655 38.290 52.935 ;
        RECT 31.415 52.335 38.315 52.655 ;
        RECT 44.470 52.580 44.790 53.280 ;
        RECT 41.045 52.550 41.365 52.580 ;
        RECT 44.470 52.550 44.805 52.580 ;
        RECT 34.560 52.305 34.880 52.335 ;
        RECT 40.505 52.230 44.805 52.550 ;
        RECT 41.045 52.200 41.365 52.230 ;
        RECT 44.485 52.200 44.805 52.230 ;
        RECT 32.100 51.095 33.060 51.125 ;
        RECT 29.740 50.135 46.735 51.095 ;
        RECT 25.940 47.805 29.030 48.125 ;
        RECT 25.940 47.775 26.265 47.805 ;
        RECT 25.945 47.230 26.265 47.775 ;
        RECT 28.710 46.735 29.030 47.805 ;
        RECT 29.740 47.505 30.700 50.135 ;
        RECT 32.100 50.105 33.060 50.135 ;
        RECT 37.800 49.425 38.735 50.135 ;
        RECT 37.800 48.490 38.760 49.425 ;
        RECT 45.775 48.550 46.735 50.135 ;
        RECT 33.960 48.145 34.280 48.155 ;
        RECT 33.930 48.125 34.310 48.145 ;
        RECT 33.930 47.825 36.020 48.125 ;
        RECT 33.960 47.805 36.020 47.825 ;
        RECT 33.960 47.635 34.285 47.805 ;
        RECT 33.935 47.315 34.315 47.635 ;
        RECT 33.960 46.735 34.280 47.315 ;
        RECT 35.700 47.135 36.020 47.805 ;
        RECT 37.770 47.530 38.790 48.490 ;
        RECT 41.960 48.185 42.280 48.215 ;
        RECT 39.580 47.865 44.770 48.185 ;
        RECT 39.580 47.135 39.900 47.865 ;
        RECT 41.960 47.835 42.285 47.865 ;
        RECT 41.965 47.690 42.285 47.835 ;
        RECT 41.935 47.370 42.315 47.690 ;
        RECT 35.700 46.815 39.900 47.135 ;
        RECT 44.450 47.310 44.770 47.865 ;
        RECT 45.745 47.590 46.765 48.550 ;
        RECT 51.650 47.340 51.970 47.830 ;
        RECT 51.570 47.310 51.970 47.340 ;
        RECT 44.450 46.990 51.970 47.310 ;
        RECT 51.570 46.960 51.890 46.990 ;
        RECT 28.710 46.415 34.280 46.735 ;
        RECT 31.115 25.785 31.430 25.805 ;
        RECT 30.140 25.420 31.455 25.785 ;
        RECT 31.115 25.400 31.430 25.420 ;
        RECT 52.320 23.750 53.280 57.840 ;
        RECT 66.525 27.860 67.250 29.105 ;
        RECT 66.505 27.185 67.270 27.860 ;
        RECT 66.525 25.250 67.250 27.185 ;
        RECT 66.525 24.870 67.470 25.250 ;
        RECT 66.525 24.650 67.250 24.870 ;
        RECT 66.525 24.270 67.470 24.650 ;
        RECT 66.525 24.120 67.250 24.270 ;
        RECT 52.320 22.790 53.325 23.750 ;
        RECT 73.660 22.225 73.980 22.790 ;
        RECT 73.660 21.990 74.975 22.225 ;
        RECT 73.630 21.675 74.975 21.990 ;
        RECT 73.630 21.670 74.010 21.675 ;
        RECT 74.425 18.295 74.975 21.675 ;
        RECT 76.070 19.990 77.030 61.830 ;
        RECT 84.920 46.985 85.365 60.325 ;
        RECT 84.880 46.250 85.365 46.985 ;
        RECT 84.880 43.310 85.235 46.250 ;
        RECT 84.860 43.005 85.255 43.310 ;
        RECT 84.880 42.980 85.235 43.005 ;
        RECT 78.815 40.270 79.725 40.290 ;
        RECT 80.305 40.270 81.215 40.290 ;
        RECT 78.790 40.240 85.210 40.270 ;
        RECT 78.790 39.310 85.260 40.240 ;
        RECT 139.270 39.560 139.550 39.595 ;
        RECT 78.815 39.290 79.725 39.310 ;
        RECT 80.305 39.290 81.215 39.310 ;
        RECT 84.250 39.265 85.260 39.310 ;
        RECT 84.920 38.505 85.260 39.265 ;
        RECT 84.900 38.215 85.280 38.505 ;
        RECT 84.920 37.845 85.260 38.215 ;
        RECT 79.110 37.615 79.890 37.640 ;
        RECT 79.090 36.885 79.910 37.615 ;
        RECT 84.900 37.555 85.280 37.845 ;
        RECT 139.260 37.740 139.560 39.560 ;
        RECT 84.920 37.530 85.260 37.555 ;
        RECT 79.110 36.325 79.890 36.885 ;
        RECT 139.160 36.620 139.670 37.740 ;
        RECT 79.080 35.595 79.900 36.325 ;
        RECT 80.995 36.080 81.720 36.170 ;
        RECT 80.995 36.055 104.620 36.080 ;
        RECT 79.110 27.890 79.890 35.595 ;
        RECT 80.975 35.380 104.620 36.055 ;
        RECT 80.995 35.355 104.620 35.380 ;
        RECT 80.995 34.755 81.720 35.355 ;
        RECT 80.975 34.080 81.740 34.755 ;
        RECT 80.995 34.055 81.720 34.080 ;
        RECT 83.330 33.950 90.130 34.270 ;
        RECT 83.330 33.570 83.650 33.950 ;
        RECT 89.810 33.670 90.130 33.950 ;
        RECT 83.300 33.250 83.680 33.570 ;
        RECT 89.780 33.350 90.160 33.670 ;
        RECT 83.330 32.620 83.650 33.250 ;
        RECT 89.810 32.620 90.130 33.350 ;
        RECT 94.635 33.290 95.545 33.310 ;
        RECT 96.235 33.290 97.145 33.310 ;
        RECT 92.380 33.265 97.170 33.290 ;
        RECT 92.380 32.355 97.190 33.265 ;
        RECT 92.380 32.330 97.170 32.355 ;
        RECT 94.410 32.310 95.545 32.330 ;
        RECT 96.235 32.310 97.145 32.330 ;
        RECT 83.330 31.170 83.650 31.200 ;
        RECT 83.300 30.850 83.650 31.170 ;
        RECT 83.330 30.120 83.650 30.850 ;
        RECT 85.840 30.630 86.860 31.590 ;
        RECT 89.810 31.170 90.130 31.200 ;
        RECT 92.530 31.170 92.850 31.200 ;
        RECT 89.810 30.850 93.380 31.170 ;
        RECT 89.810 30.820 90.150 30.850 ;
        RECT 92.530 30.820 92.850 30.850 ;
        RECT 85.870 30.105 86.830 30.630 ;
        RECT 89.830 30.120 90.150 30.820 ;
        RECT 80.670 29.950 81.630 29.980 ;
        RECT 80.640 28.990 81.660 29.950 ;
        RECT 85.860 29.405 86.845 30.105 ;
        RECT 91.770 29.950 92.050 29.975 ;
        RECT 92.450 29.950 92.730 29.975 ;
        RECT 78.930 26.930 79.950 27.890 ;
        RECT 79.110 25.690 79.890 26.930 ;
        RECT 80.670 25.605 81.630 28.990 ;
        RECT 82.000 28.420 86.845 29.405 ;
        RECT 89.780 29.630 92.750 29.950 ;
        RECT 89.780 28.680 90.100 29.630 ;
        RECT 91.770 29.605 92.050 29.630 ;
        RECT 92.450 29.605 92.730 29.630 ;
        RECT 80.650 24.695 81.650 25.605 ;
        RECT 80.670 23.725 81.630 24.695 ;
        RECT 80.650 22.815 81.650 23.725 ;
        RECT 80.670 22.790 81.630 22.815 ;
        RECT 76.040 19.030 77.060 19.990 ;
        RECT 81.055 18.295 81.605 18.325 ;
        RECT 67.120 17.870 67.440 17.900 ;
        RECT 69.790 17.870 70.110 17.900 ;
        RECT 73.690 17.870 74.010 17.900 ;
        RECT 67.120 17.550 74.040 17.870 ;
        RECT 74.425 17.745 81.635 18.295 ;
        RECT 81.055 17.715 81.635 17.745 ;
        RECT 67.120 17.170 67.440 17.550 ;
        RECT 69.790 17.520 70.110 17.550 ;
        RECT 73.690 17.170 74.010 17.550 ;
        RECT 67.090 16.850 67.470 17.170 ;
        RECT 73.660 17.130 74.040 17.170 ;
        RECT 73.660 16.850 75.630 17.130 ;
        RECT 74.190 15.170 74.510 15.200 ;
        RECT 67.070 14.850 74.540 15.170 ;
        RECT 67.090 14.570 67.410 14.850 ;
        RECT 74.190 14.710 74.510 14.850 ;
        RECT 67.060 14.250 67.440 14.570 ;
        RECT 74.130 14.470 74.510 14.710 ;
        RECT 75.350 14.650 75.630 16.850 ;
        RECT 81.085 16.725 81.635 17.715 ;
        RECT 82.000 17.510 82.985 28.420 ;
        RECT 89.750 28.360 90.130 28.680 ;
        RECT 89.780 27.960 90.100 28.360 ;
        RECT 89.750 27.640 90.130 27.960 ;
        RECT 83.310 26.170 83.630 26.200 ;
        RECT 83.280 25.850 83.660 26.170 ;
        RECT 83.310 25.570 83.630 25.850 ;
        RECT 89.830 25.570 90.150 26.300 ;
        RECT 83.280 25.250 90.150 25.570 ;
        RECT 83.325 24.270 83.620 24.305 ;
        RECT 83.310 24.250 83.630 24.270 ;
        RECT 83.285 23.970 83.655 24.250 ;
        RECT 89.830 23.990 90.150 25.250 ;
        RECT 94.410 23.990 95.370 32.310 ;
        RECT 104.330 31.170 104.610 35.355 ;
        RECT 133.340 34.980 134.220 35.010 ;
        RECT 135.265 34.980 136.095 35.000 ;
        RECT 131.720 34.100 136.120 34.980 ;
        RECT 133.340 34.070 134.220 34.100 ;
        RECT 135.240 33.475 136.120 34.100 ;
        RECT 135.220 32.645 136.140 33.475 ;
        RECT 135.240 32.620 136.120 32.645 ;
        RECT 131.250 31.970 131.550 32.000 ;
        RECT 131.250 31.670 139.680 31.970 ;
        RECT 131.250 31.640 131.550 31.670 ;
        RECT 96.280 30.850 96.660 31.170 ;
        RECT 104.300 30.850 104.680 31.170 ;
        RECT 96.310 30.570 96.630 30.850 ;
        RECT 104.330 30.570 104.650 30.850 ;
        RECT 112.330 30.570 112.650 31.300 ;
        RECT 96.280 30.250 112.680 30.570 ;
        RECT 96.310 30.220 96.630 30.250 ;
        RECT 104.330 30.220 104.650 30.250 ;
        RECT 112.330 30.220 112.650 30.250 ;
        RECT 132.540 29.970 133.420 30.310 ;
        RECT 135.240 29.970 136.120 30.310 ;
        RECT 96.310 28.470 96.630 29.965 ;
        RECT 98.810 28.530 121.830 29.490 ;
        RECT 130.740 29.070 131.620 29.110 ;
        RECT 130.740 28.770 132.240 29.070 ;
        RECT 96.280 28.150 96.660 28.470 ;
        RECT 96.310 27.920 96.630 28.150 ;
        RECT 96.280 27.600 96.660 27.920 ;
        RECT 98.810 27.300 99.770 28.530 ;
        RECT 111.870 28.070 112.830 28.100 ;
        RECT 104.110 27.690 105.020 27.735 ;
        RECT 102.465 26.730 106.330 27.690 ;
        RECT 111.870 27.110 119.400 28.070 ;
        RECT 111.870 27.080 112.830 27.110 ;
        RECT 104.110 26.685 105.020 26.730 ;
        RECT 96.310 25.630 96.630 26.310 ;
        RECT 102.810 26.270 103.130 26.300 ;
        RECT 102.780 25.950 104.650 26.270 ;
        RECT 102.810 25.670 103.130 25.950 ;
        RECT 96.280 25.310 96.660 25.630 ;
        RECT 102.780 25.350 103.160 25.670 ;
        RECT 96.310 23.990 96.630 25.310 ;
        RECT 104.330 24.890 104.650 25.950 ;
        RECT 105.370 25.600 106.330 26.730 ;
        RECT 109.300 24.890 109.620 26.030 ;
        RECT 115.780 25.740 116.160 26.060 ;
        RECT 115.810 25.480 116.130 25.740 ;
        RECT 116.410 25.490 117.370 26.520 ;
        RECT 115.780 25.160 116.160 25.480 ;
        RECT 104.330 24.840 109.620 24.890 ;
        RECT 115.160 24.860 115.440 24.905 ;
        RECT 115.810 24.860 116.130 25.160 ;
        RECT 104.330 24.570 109.625 24.840 ;
        RECT 108.530 24.515 108.810 24.570 ;
        RECT 109.255 24.560 109.625 24.570 ;
        RECT 109.300 24.515 109.580 24.560 ;
        RECT 114.465 24.540 116.130 24.860 ;
        RECT 115.160 24.495 115.440 24.540 ;
        RECT 83.310 22.670 83.630 23.970 ;
        RECT 85.870 23.030 99.870 23.990 ;
        RECT 83.280 22.350 83.660 22.670 ;
        RECT 85.870 22.490 86.830 23.030 ;
        RECT 83.310 21.970 83.630 22.350 ;
        RECT 83.280 21.650 83.660 21.970 ;
        RECT 85.840 21.530 86.860 22.490 ;
        RECT 83.950 21.190 84.910 21.220 ;
        RECT 88.310 21.190 91.400 22.090 ;
        RECT 92.410 21.200 93.370 23.030 ;
        RECT 83.950 21.130 91.400 21.190 ;
        RECT 83.950 20.230 89.270 21.130 ;
        RECT 94.710 20.930 98.000 21.890 ;
        RECT 98.910 21.300 99.870 23.030 ;
        RECT 102.810 22.670 103.130 24.015 ;
        RECT 103.525 22.845 107.655 23.375 ;
        RECT 111.910 23.030 112.770 23.800 ;
        RECT 102.780 22.350 103.160 22.670 ;
        RECT 102.810 21.970 103.130 22.350 ;
        RECT 102.780 21.650 103.160 21.970 ;
        RECT 103.525 21.390 104.055 22.845 ;
        RECT 107.125 22.390 107.655 22.845 ;
        RECT 90.450 20.890 91.410 20.920 ;
        RECT 94.710 20.890 95.670 20.930 ;
        RECT 83.950 20.200 84.910 20.230 ;
        RECT 89.830 20.170 90.150 20.200 ;
        RECT 83.280 19.850 83.660 20.170 ;
        RECT 89.800 19.850 90.180 20.170 ;
        RECT 90.450 19.930 95.670 20.890 ;
        RECT 90.450 19.900 91.410 19.930 ;
        RECT 83.310 19.470 83.630 19.850 ;
        RECT 89.830 19.470 90.150 19.850 ;
        RECT 96.330 19.470 96.650 20.200 ;
        RECT 96.910 19.590 97.870 20.620 ;
        RECT 101.110 20.430 104.500 21.390 ;
        RECT 105.410 21.290 106.370 22.220 ;
        RECT 107.125 21.860 110.940 22.390 ;
        RECT 111.810 22.370 112.770 23.030 ;
        RECT 115.810 22.370 116.130 24.540 ;
        RECT 116.410 24.530 119.910 25.490 ;
        RECT 118.950 23.690 119.910 24.530 ;
        RECT 120.870 23.790 121.830 28.530 ;
        RECT 131.940 25.870 132.240 28.770 ;
        RECT 135.240 27.570 136.120 27.910 ;
        RECT 132.540 26.770 133.420 27.110 ;
        RECT 137.040 25.870 137.920 25.910 ;
        RECT 131.940 25.570 137.920 25.870 ;
        RECT 132.540 24.370 133.420 24.710 ;
        RECT 135.240 24.370 136.120 24.710 ;
        RECT 118.920 22.730 119.940 23.690 ;
        RECT 120.840 22.830 121.860 23.790 ;
        RECT 139.380 23.770 139.680 31.670 ;
        RECT 137.540 23.470 139.680 23.770 ;
        RECT 132.540 22.770 133.420 23.110 ;
        RECT 135.240 22.770 136.120 23.110 ;
        RECT 111.770 22.050 121.750 22.370 ;
        RECT 111.810 21.290 112.770 22.050 ;
        RECT 118.310 21.670 118.650 22.050 ;
        RECT 118.280 21.350 118.660 21.670 ;
        RECT 101.110 19.590 102.070 20.430 ;
        RECT 105.410 20.330 112.770 21.290 ;
        RECT 118.330 20.720 118.650 21.350 ;
        RECT 120.930 20.370 121.250 21.900 ;
        RECT 121.430 21.220 121.750 22.050 ;
        RECT 132.540 20.370 133.420 20.710 ;
        RECT 135.240 20.370 136.120 20.710 ;
        RECT 102.810 20.170 103.130 20.200 ;
        RECT 118.310 20.170 121.250 20.370 ;
        RECT 102.780 19.850 103.160 20.170 ;
        RECT 102.810 19.670 103.130 19.850 ;
        RECT 83.280 19.150 96.680 19.470 ;
        RECT 83.310 19.120 83.630 19.150 ;
        RECT 89.830 19.120 90.150 19.150 ;
        RECT 96.910 18.630 102.070 19.590 ;
        RECT 102.780 19.350 103.160 19.670 ;
        RECT 109.330 19.570 109.650 20.100 ;
        RECT 118.280 20.050 121.250 20.170 ;
        RECT 137.540 20.070 137.840 23.470 ;
        RECT 118.280 19.850 118.660 20.050 ;
        RECT 109.300 19.350 109.680 19.570 ;
        RECT 102.810 19.250 109.680 19.350 ;
        RECT 102.810 19.030 109.650 19.250 ;
        RECT 118.330 19.220 118.650 19.850 ;
        RECT 120.870 19.790 121.830 19.820 ;
        RECT 102.810 18.750 103.130 19.030 ;
        RECT 119.510 18.830 121.830 19.790 ;
        RECT 137.510 19.770 137.870 20.070 ;
        RECT 137.540 19.540 137.840 19.770 ;
        RECT 137.510 19.240 137.870 19.540 ;
        RECT 137.540 19.190 137.840 19.240 ;
        RECT 83.280 18.250 83.660 18.570 ;
        RECT 98.870 18.290 99.830 18.630 ;
        RECT 102.780 18.430 103.160 18.750 ;
        RECT 119.510 18.690 120.470 18.830 ;
        RECT 120.870 18.800 121.830 18.830 ;
        RECT 83.310 18.070 83.630 18.250 ;
        RECT 83.280 17.750 83.660 18.070 ;
        RECT 83.310 17.510 83.630 17.750 ;
        RECT 85.895 17.510 86.880 18.230 ;
        RECT 82.000 16.525 86.880 17.510 ;
        RECT 92.380 17.330 99.860 18.290 ;
        RECT 102.810 17.720 103.130 18.430 ;
        RECT 109.280 18.250 109.660 18.570 ;
        RECT 109.310 17.970 109.630 18.250 ;
        RECT 114.910 18.090 120.470 18.690 ;
        RECT 108.730 17.650 109.630 17.970 ;
        RECT 108.730 17.270 109.050 17.650 ;
        RECT 109.310 17.620 109.630 17.650 ;
        RECT 111.880 17.730 120.470 18.090 ;
        RECT 101.030 16.950 109.050 17.270 ;
        RECT 111.880 17.130 115.870 17.730 ;
        RECT 120.840 17.130 121.860 18.090 ;
        RECT 132.540 17.970 133.420 18.310 ;
        RECT 135.240 17.970 136.120 18.310 ;
        RECT 101.030 16.770 101.350 16.950 ;
        RECT 82.000 16.505 82.985 16.525 ;
        RECT 83.310 16.505 83.630 16.525 ;
        RECT 88.130 16.450 101.350 16.770 ;
        RECT 83.330 16.170 83.650 16.200 ;
        RECT 88.130 16.170 88.450 16.450 ;
        RECT 83.300 15.850 88.450 16.170 ;
        RECT 83.330 15.220 83.650 15.850 ;
        RECT 89.830 15.470 90.150 16.100 ;
        RECT 96.280 15.850 96.660 16.170 ;
        RECT 96.310 15.470 96.630 15.850 ;
        RECT 109.970 15.610 110.930 16.560 ;
        RECT 118.310 16.070 118.630 16.100 ;
        RECT 120.870 16.070 121.830 17.130 ;
        RECT 130.110 16.160 130.470 16.460 ;
        RECT 132.540 16.370 133.420 16.710 ;
        RECT 135.240 16.370 136.120 16.710 ;
        RECT 118.310 15.830 121.830 16.070 ;
        RECT 118.310 15.750 121.750 15.830 ;
        RECT 118.310 15.720 118.650 15.750 ;
        RECT 89.730 15.150 96.660 15.470 ;
        RECT 89.830 15.120 90.150 15.150 ;
        RECT 96.310 15.120 96.630 15.150 ;
        RECT 89.850 14.650 90.130 15.120 ;
        RECT 74.130 14.150 74.540 14.470 ;
        RECT 75.350 14.370 90.130 14.650 ;
        RECT 104.210 14.650 110.930 15.610 ;
        RECT 118.330 15.220 118.650 15.720 ;
        RECT 130.140 15.450 130.440 16.160 ;
        RECT 135.240 15.570 136.120 15.910 ;
        RECT 130.110 15.150 130.470 15.450 ;
        RECT 74.130 13.770 74.450 14.150 ;
        RECT 83.330 13.770 83.650 13.800 ;
        RECT 104.210 13.790 105.170 14.650 ;
        RECT 120.870 14.190 121.830 14.220 ;
        RECT 74.130 13.670 91.650 13.770 ;
        RECT 99.310 13.670 99.630 13.700 ;
        RECT 74.130 13.450 99.660 13.670 ;
        RECT 83.330 12.720 83.650 13.450 ;
        RECT 91.300 13.350 99.660 13.450 ;
        RECT 91.330 13.070 91.650 13.350 ;
        RECT 99.310 13.070 99.630 13.350 ;
        RECT 91.300 12.750 91.680 13.070 ;
        RECT 99.280 12.750 99.660 13.070 ;
        RECT 103.180 12.830 105.170 13.790 ;
        RECT 107.310 13.850 118.650 14.170 ;
        RECT 107.310 13.570 107.650 13.850 ;
        RECT 107.280 13.250 107.660 13.570 ;
        RECT 91.330 12.720 91.650 12.750 ;
        RECT 104.210 12.390 105.170 12.830 ;
        RECT 107.330 12.620 107.650 13.250 ;
        RECT 118.330 12.720 118.650 13.850 ;
        RECT 120.870 13.230 125.270 14.190 ;
        RECT 120.870 13.200 121.830 13.230 ;
        RECT 104.210 11.690 108.910 12.390 ;
        RECT 130.140 11.790 130.440 15.150 ;
        RECT 132.540 13.970 133.420 14.310 ;
        RECT 135.240 13.970 136.120 14.310 ;
        RECT 132.540 13.170 133.420 13.510 ;
        RECT 135.240 13.170 136.120 13.510 ;
        RECT 132.540 12.370 133.420 12.710 ;
        RECT 135.240 12.370 136.120 12.710 ;
        RECT 134.350 11.800 134.630 11.835 ;
        RECT 135.270 11.800 135.570 11.835 ;
        RECT 134.340 11.790 135.570 11.800 ;
        RECT 104.210 11.430 108.940 11.690 ;
        RECT 130.140 11.490 135.570 11.790 ;
        RECT 134.350 11.465 134.630 11.490 ;
        RECT 135.270 11.465 135.570 11.490 ;
        RECT 81.035 10.075 81.585 10.945 ;
        RECT 107.920 10.730 108.940 11.430 ;
        RECT 132.540 11.295 133.420 11.320 ;
        RECT 124.785 10.075 125.335 10.885 ;
        RECT 132.520 10.465 133.440 11.295 ;
        RECT 81.035 10.045 81.605 10.075 ;
        RECT 124.785 10.045 125.345 10.075 ;
        RECT 81.035 9.495 125.345 10.045 ;
        RECT 129.290 9.750 130.170 9.780 ;
        RECT 132.540 9.750 133.420 10.465 ;
        RECT 81.055 9.465 81.605 9.495 ;
        RECT 124.795 9.465 125.345 9.495 ;
        RECT 129.190 9.725 133.420 9.750 ;
        RECT 129.190 8.895 133.440 9.725 ;
        RECT 129.190 8.870 133.420 8.895 ;
        RECT 129.290 8.840 130.170 8.870 ;
        RECT 91.955 7.140 92.910 7.145 ;
        RECT 83.980 6.200 84.880 7.040 ;
        RECT 84.010 5.720 84.850 6.200 ;
        RECT 91.930 6.195 92.935 7.140 ;
        RECT 83.980 4.880 84.880 5.720 ;
        RECT 84.010 3.735 84.850 4.880 ;
        RECT 91.955 4.690 92.910 6.195 ;
        RECT 99.920 5.180 100.940 7.070 ;
        RECT 91.910 3.785 92.955 4.690 ;
        RECT 83.990 2.735 84.870 3.525 ;
        RECT 91.955 2.540 92.910 3.785 ;
        RECT 99.950 3.605 100.910 5.180 ;
        RECT 99.930 2.695 100.930 3.605 ;
        RECT 131.780 3.295 132.540 8.870 ;
        RECT 131.760 2.585 132.560 3.295 ;
        RECT 131.780 2.560 132.540 2.585 ;
      LAYER met3 ;
        RECT 138.270 108.140 138.680 109.170 ;
        RECT 49.950 107.680 50.330 107.690 ;
        RECT 140.865 107.680 141.195 107.695 ;
        RECT 49.950 107.380 141.195 107.680 ;
        RECT 49.950 107.370 50.330 107.380 ;
        RECT 140.865 107.365 141.195 107.380 ;
        RECT 142.580 103.060 143.460 107.430 ;
        RECT 145.280 104.230 146.160 108.640 ;
        RECT 159.380 107.580 160.510 108.820 ;
        RECT 156.710 102.760 158.090 104.200 ;
        RECT 6.270 97.540 78.790 97.920 ;
        RECT 0.140 95.800 78.790 97.540 ;
        RECT 6.270 95.420 78.790 95.800 ;
        RECT 5.045 92.090 6.225 92.115 ;
        RECT 2.700 90.910 6.225 92.090 ;
        RECT 5.045 90.885 6.225 90.910 ;
        RECT 20.340 90.370 46.840 90.770 ;
        RECT 20.340 88.670 20.740 90.370 ;
        RECT 67.770 89.910 68.650 93.860 ;
        RECT 75.355 92.140 76.315 92.215 ;
        RECT 76.805 92.140 77.765 92.215 ;
        RECT 69.770 91.260 86.060 92.140 ;
        RECT 75.355 91.205 76.315 91.260 ;
        RECT 76.805 91.205 77.765 91.260 ;
        RECT 67.770 89.030 83.360 89.910 ;
        RECT 10.040 83.270 15.440 88.670 ;
        RECT 17.840 83.270 23.240 88.670 ;
        RECT 12.540 80.870 12.940 83.270 ;
        RECT 20.340 80.870 20.740 83.270 ;
        RECT 10.040 75.970 15.440 80.870 ;
        RECT 17.840 75.970 23.240 80.870 ;
        RECT 10.040 75.470 23.240 75.970 ;
        RECT 10.040 68.785 15.440 74.185 ;
        RECT 17.840 68.785 23.240 74.185 ;
        RECT 12.540 66.385 12.940 68.785 ;
        RECT 20.340 66.385 20.740 68.785 ;
        RECT 10.040 61.485 15.440 66.385 ;
        RECT 17.840 61.485 23.240 66.385 ;
        RECT 10.040 60.985 23.240 61.485 ;
        RECT 37.075 57.415 37.440 58.050 ;
        RECT 1.990 56.865 4.630 57.180 ;
        RECT 37.070 57.085 37.440 57.415 ;
        RECT 0.380 55.500 4.630 56.865 ;
        RECT 1.990 55.180 4.630 55.500 ;
        RECT 26.160 55.135 26.480 55.165 ;
        RECT 30.330 55.135 30.660 55.160 ;
        RECT 31.215 55.135 31.545 55.140 ;
        RECT 22.365 54.815 31.545 55.135 ;
        RECT 26.160 54.785 26.480 54.815 ;
        RECT 30.330 54.790 30.660 54.815 ;
        RECT 31.215 54.810 31.545 54.815 ;
        RECT 2.365 51.495 4.630 53.495 ;
        RECT 37.075 43.285 37.440 57.085 ;
        RECT 34.090 42.920 37.440 43.285 ;
        RECT 34.090 25.785 34.455 42.920 ;
        RECT 66.525 34.780 67.250 88.050 ;
        RECT 73.035 86.680 73.915 86.705 ;
        RECT 75.080 86.680 75.960 89.030 ;
        RECT 73.035 85.800 75.960 86.680 ;
        RECT 73.035 85.775 73.915 85.800 ;
        RECT 68.395 85.025 68.765 85.355 ;
        RECT 82.480 85.055 83.360 89.030 ;
        RECT 85.180 85.680 86.060 91.260 ;
        RECT 85.180 85.280 86.190 85.680 ;
        RECT 68.420 84.455 68.740 85.025 ;
        RECT 82.435 84.655 83.410 85.055 ;
        RECT 68.415 84.125 68.745 84.455 ;
        RECT 68.420 66.295 68.740 84.125 ;
        RECT 82.480 82.470 83.360 84.655 ;
        RECT 85.180 82.470 86.060 85.280 ;
        RECT 82.480 80.870 83.380 82.470 ;
        RECT 85.180 80.870 86.080 82.470 ;
        RECT 69.235 79.650 70.195 79.675 ;
        RECT 70.825 79.650 71.785 79.675 ;
        RECT 69.235 78.690 77.020 79.650 ;
        RECT 69.235 78.665 70.195 78.690 ;
        RECT 70.825 78.665 71.785 78.690 ;
        RECT 69.295 76.275 70.255 77.285 ;
        RECT 70.855 77.260 71.815 77.285 ;
        RECT 70.855 76.300 74.240 77.260 ;
        RECT 70.855 76.275 71.815 76.300 ;
        RECT 73.280 70.500 74.240 76.300 ;
        RECT 76.060 72.950 77.020 78.690 ;
        RECT 82.480 74.680 83.360 80.870 ;
        RECT 85.180 75.520 86.060 80.870 ;
        RECT 100.295 80.190 100.625 80.205 ;
        RECT 138.300 80.190 138.620 80.230 ;
        RECT 100.295 79.890 138.620 80.190 ;
        RECT 100.295 79.875 100.625 79.890 ;
        RECT 138.300 79.850 138.620 79.890 ;
        RECT 78.440 72.950 83.840 73.020 ;
        RECT 76.060 71.990 83.840 72.950 ;
        RECT 73.280 69.540 76.400 70.500 ;
        RECT 68.395 66.290 68.765 66.295 ;
        RECT 69.065 66.290 69.395 66.295 ;
        RECT 68.395 65.970 69.395 66.290 ;
        RECT 68.395 65.965 68.765 65.970 ;
        RECT 69.065 65.965 69.395 65.970 ;
        RECT 75.440 40.270 76.400 69.540 ;
        RECT 78.440 67.620 83.840 71.990 ;
        RECT 86.240 67.620 91.640 73.020 ;
        RECT 80.940 65.220 81.340 67.620 ;
        RECT 88.740 65.220 89.140 67.620 ;
        RECT 78.440 60.720 83.840 65.220 ;
        RECT 78.420 60.320 83.840 60.720 ;
        RECT 86.240 60.320 91.640 65.220 ;
        RECT 78.420 59.820 91.640 60.320 ;
        RECT 78.420 57.990 79.380 59.820 ;
        RECT 78.420 52.590 83.820 57.990 ;
        RECT 86.220 52.590 91.620 57.990 ;
        RECT 80.920 50.190 81.320 52.590 ;
        RECT 88.720 50.190 89.120 52.590 ;
        RECT 78.420 45.290 83.820 50.190 ;
        RECT 86.220 45.290 91.620 50.190 ;
        RECT 78.420 44.790 91.620 45.290 ;
        RECT 84.880 42.085 85.235 43.720 ;
        RECT 83.295 41.730 85.235 42.085 ;
        RECT 75.440 39.310 81.240 40.270 ;
        RECT 83.295 37.640 83.650 41.730 ;
        RECT 84.920 40.245 85.260 40.280 ;
        RECT 84.225 39.285 85.260 40.245 ;
        RECT 79.100 36.860 83.650 37.640 ;
        RECT 79.100 35.570 79.880 36.860 ;
        RECT 80.970 35.420 81.745 36.145 ;
        RECT 80.995 34.780 81.720 35.420 ;
        RECT 66.525 34.055 81.720 34.780 ;
        RECT 66.525 29.085 67.250 34.055 ;
        RECT 66.500 28.360 67.275 29.085 ;
        RECT 66.525 27.160 67.250 28.360 ;
        RECT 31.090 25.420 34.455 25.785 ;
        RECT 80.670 25.575 81.630 25.630 ;
        RECT 80.645 24.615 81.655 25.575 ;
        RECT 52.345 23.750 53.305 23.775 ;
        RECT 80.670 23.750 81.630 24.615 ;
        RECT 83.295 23.935 83.650 36.860 ;
        RECT 84.920 25.180 85.260 39.285 ;
        RECT 94.140 39.560 94.460 39.600 ;
        RECT 139.245 39.560 139.575 39.575 ;
        RECT 94.140 39.260 139.575 39.560 ;
        RECT 94.140 39.220 94.460 39.260 ;
        RECT 139.245 39.245 139.575 39.260 ;
        RECT 135.240 34.955 136.120 34.980 ;
        RECT 135.215 34.075 136.145 34.955 ;
        RECT 94.610 32.330 101.870 33.290 ;
        RECT 91.745 29.950 92.075 29.955 ;
        RECT 92.425 29.950 92.755 29.955 ;
        RECT 91.745 29.945 96.630 29.950 ;
        RECT 91.745 29.630 96.655 29.945 ;
        RECT 91.745 29.625 92.075 29.630 ;
        RECT 92.425 29.625 92.755 29.630 ;
        RECT 96.285 29.615 96.655 29.630 ;
        RECT 96.310 29.275 96.630 29.615 ;
        RECT 96.285 28.945 96.655 29.275 ;
        RECT 100.910 27.690 101.870 32.330 ;
        RECT 102.485 27.690 103.445 27.715 ;
        RECT 100.910 26.730 103.445 27.690 ;
        RECT 102.485 26.705 103.445 26.730 ;
        RECT 104.085 26.705 105.045 27.715 ;
        RECT 84.920 24.840 103.140 25.180 ;
        RECT 102.800 23.995 103.140 24.840 ;
        RECT 108.505 24.860 108.835 24.865 ;
        RECT 109.275 24.860 109.605 24.865 ;
        RECT 114.485 24.860 114.815 24.885 ;
        RECT 115.135 24.860 115.465 24.885 ;
        RECT 108.505 24.540 115.465 24.860 ;
        RECT 108.505 24.535 108.835 24.540 ;
        RECT 109.275 24.535 109.605 24.540 ;
        RECT 114.485 24.515 114.815 24.540 ;
        RECT 115.135 24.515 115.465 24.540 ;
        RECT 52.345 22.790 81.630 23.750 ;
        RECT 83.305 23.595 83.635 23.935 ;
        RECT 102.785 23.665 103.155 23.995 ;
        RECT 83.285 23.265 83.655 23.595 ;
        RECT 102.800 22.940 103.140 23.665 ;
        RECT 52.345 22.765 53.305 22.790 ;
        RECT 132.540 9.795 133.420 31.320 ;
        RECT 134.325 11.800 134.655 11.815 ;
        RECT 135.240 11.800 136.120 34.075 ;
        RECT 134.325 11.500 136.120 11.800 ;
        RECT 134.325 11.485 134.655 11.500 ;
        RECT 132.515 8.915 133.445 9.795 ;
        RECT 132.540 8.870 133.420 8.915 ;
        RECT 135.240 6.880 136.120 11.500 ;
        RECT 83.900 4.400 85.010 4.750 ;
        RECT 91.890 4.400 93.060 4.780 ;
        RECT 99.870 4.400 101.040 4.730 ;
        RECT 2.400 2.400 158.600 4.400 ;
        RECT 0.000 0.000 161.000 2.000 ;
      LAYER met4 ;
        RECT 30.670 109.450 30.970 110.520 ;
        RECT 33.430 109.430 33.730 110.520 ;
        RECT 36.190 109.520 36.490 110.520 ;
        RECT 38.950 109.540 39.250 110.520 ;
        RECT 41.710 109.480 42.010 110.520 ;
        RECT 44.470 109.430 44.770 110.520 ;
        RECT 47.230 109.400 47.530 110.520 ;
        RECT 49.990 109.360 50.290 110.520 ;
        RECT 30.670 108.400 30.970 109.150 ;
        RECT 33.430 108.400 33.730 109.130 ;
        RECT 36.190 108.400 36.490 109.220 ;
        RECT 38.950 108.400 39.250 109.240 ;
        RECT 41.710 108.400 42.010 109.180 ;
        RECT 44.470 108.400 44.770 109.130 ;
        RECT 47.230 108.400 47.530 109.100 ;
        RECT 49.990 108.400 50.290 109.060 ;
        RECT 30.670 108.100 50.500 108.400 ;
        RECT 44.470 108.080 44.770 108.100 ;
        RECT 49.990 107.695 50.290 108.100 ;
        RECT 49.975 107.365 50.305 107.695 ;
        RECT 10.040 83.270 15.440 88.670 ;
        RECT 17.840 83.270 23.240 88.670 ;
        RECT 12.540 80.870 12.940 83.270 ;
        RECT 20.340 80.870 20.740 83.270 ;
        RECT 10.040 75.970 15.440 80.870 ;
        RECT 17.840 75.970 23.240 80.870 ;
        RECT 10.040 75.470 23.240 75.970 ;
        RECT 10.040 68.785 15.440 74.185 ;
        RECT 12.540 66.385 12.940 68.785 ;
        RECT 10.040 61.485 15.440 66.385 ;
        RECT 16.590 61.485 17.090 75.470 ;
        RECT 82.475 74.705 83.365 75.585 ;
        RECT 17.840 68.785 23.240 74.185 ;
        RECT 82.480 73.020 83.360 74.705 ;
        RECT 20.340 66.385 20.740 68.785 ;
        RECT 78.440 67.620 83.840 73.020 ;
        RECT 86.240 67.620 91.640 73.020 ;
        RECT 17.840 61.485 23.240 66.385 ;
        RECT 80.940 65.220 81.340 67.620 ;
        RECT 88.740 65.220 89.140 67.620 ;
        RECT 10.040 60.985 23.240 61.485 ;
        RECT 22.365 55.135 22.685 60.985 ;
        RECT 78.440 60.320 83.840 65.220 ;
        RECT 86.240 60.320 91.640 65.220 ;
        RECT 78.440 59.820 91.640 60.320 ;
        RECT 82.420 57.990 83.300 59.820 ;
        RECT 25.390 55.135 25.720 55.140 ;
        RECT 26.155 55.135 26.485 55.140 ;
        RECT 22.365 54.815 26.485 55.135 ;
        RECT 25.390 54.810 25.720 54.815 ;
        RECT 26.155 54.810 26.485 54.815 ;
        RECT 2.390 51.490 2.400 53.500 ;
        RECT 78.420 52.590 83.820 57.990 ;
        RECT 86.220 52.590 91.620 57.990 ;
        RECT 80.920 50.190 81.320 52.590 ;
        RECT 88.720 50.190 89.120 52.590 ;
        RECT 78.420 45.290 83.820 50.190 ;
        RECT 86.220 45.290 91.620 50.190 ;
        RECT 78.420 44.790 91.620 45.290 ;
        RECT 94.150 39.575 94.450 110.520 ;
        RECT 138.310 109.085 138.610 110.520 ;
        RECT 138.295 108.755 138.625 109.085 ;
        RECT 138.310 80.205 138.610 108.755 ;
        RECT 138.295 79.875 138.625 80.205 ;
        RECT 94.135 39.245 94.465 39.575 ;
        RECT 156.600 0.000 158.600 111.520 ;
        RECT 159.000 0.000 161.000 111.520 ;
  END
END tt_um_lelo_gr03_analogicus
END LIBRARY

